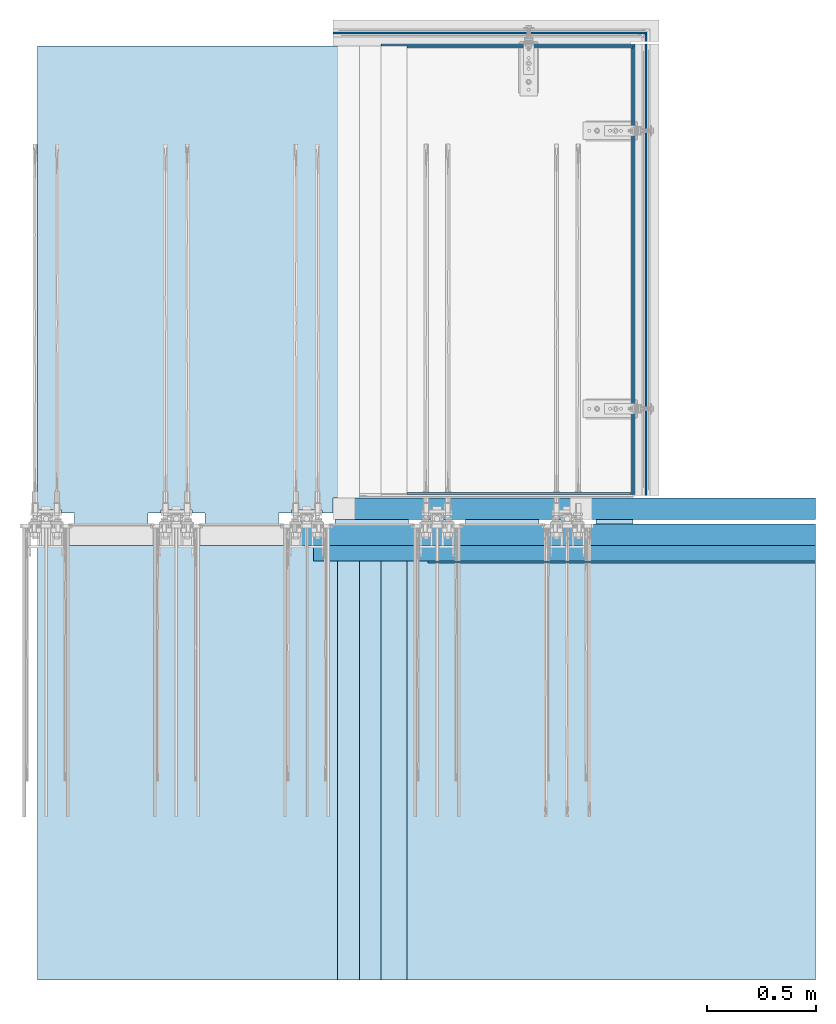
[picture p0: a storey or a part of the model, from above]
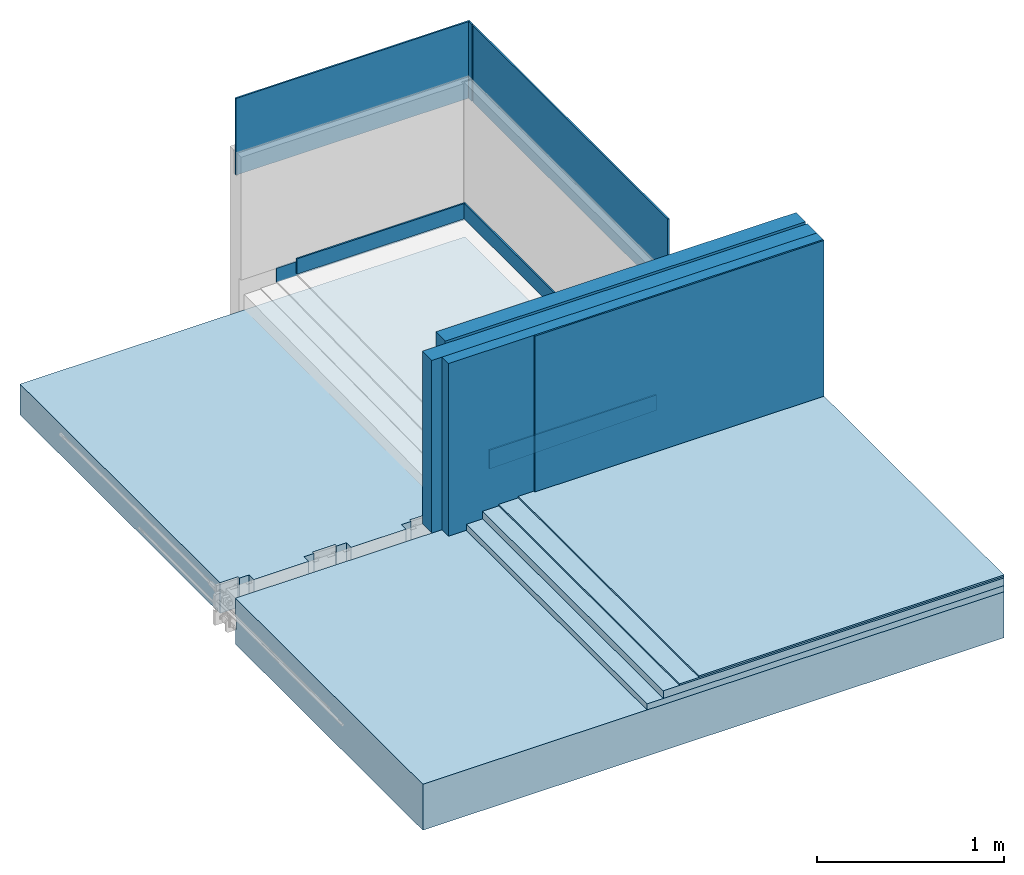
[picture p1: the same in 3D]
Properties of the parts of a building model (IFC2X3), part 1 of 2

# File
Description: ViewDefinition [CoordinationView_V2.0, QuantityTakeOffAddOnView], RevitIdentifiers [ContentGUID: 704ee8e6-b7a5-4cdf-b516-c9cadaf13e75, VersionGUID: 24b7fbaf-eea0-4a53-a88f-534976aedb0a, NumberOfSaves: 71], CoordinateReference [CoordinateBase: Shared Coordinates, ProjectSite: Internal]
File name: Solucion balcón prefabricado.ifc
Time: 2026-03-23T12:44:45+01:00
Written by: ODA SDAI 24.6
Made in: Autodesk Revit 24.3.40.26 (ESP) - IFC 24.3.20.0

# IfcProject, 000000
LongName: Solución de balcón prefabricado

# IfcSite, Default
RefLatitude: 40, 25, 13, 9643; RefLongitude: -3, -42, -20, -772056; RefElevation: 0 m
Otra - Categoría: Información de proyecto; Dirección de proyecto: Parque Empresarial de A Pontenova , Parcelas 33-39 , 27720 · A Pontenova · (Lugo); Fecha de emisión de proyecto: 13-02-2026; Nombre de cliente: Recense; Nombre de proyecto: Solución de balcón prefabricado; Número de proyecto: 000000
Datos de identidad - Autor: Deliprogal SL; Descripción de organización: Fijaciones a medida para prefabricado; Nombre de organización: Recense

# IfcBuilding
Pset_BuildingCommon - NumberOfStoreys: 1
Otra - Categoría: Información de proyecto; Dirección de proyecto: Parque Empresarial de A Pontenova , Parcelas 33-39 , 27720 · A Pontenova · (Lugo); Fecha de emisión de proyecto: 13-02-2026; Nombre de cliente: Recense; Nombre de proyecto: Solución de balcón prefabricado; Número de proyecto: 000000
Datos de identidad - Autor: Deliprogal SL; Descripción de organización: Fijaciones a medida para prefabricado; Nombre de organización: Recense

# IfcBuildingStorey: Nivel:8mm Head, L0
LongName: L0; Elevation: 0 m
Otra - Categoría: Niveles; Familia: Nivel; Familia y tipo: Nivel: 8mm Head; ID de tipo: 305; Tipo: 8mm Head
Restricciones - Elevación: 0 m
Cotas - Altura de cálculo: 0 m
Datos de identidad - Estructura: no; Nombre: L0; Planta de edificio: yes
Otra(Tipo) - Categoría: Niveles; Nombre de familia: Nivel
Restricciones(Tipo) - Base de elevación: Punto base del proyecto
Gráficos(Tipo) - Color: 12615680; Grosor de línea: 1; Patrón de línea: Dash dot; Símbolo en extremo 1 por defecto: no; Símbolo en extremo 2 por defecto: yes
Datos de identidad(Tipo) - Nombre de tipo: 8mm Head

# IfcBuildingElementProxy: Calzo termoplastico:Calzo termoplastico, Calzo termoplastico:Calzo termoplastico:3849835
In: L0
Type - Material: Caucho, butilo
Type - Otra - Categoría: Modelos genéricos; Nombre de familia: Calzo termoplastico
Type - Datos de identidad - Nombre de tipo: Calzo termoplastico
Pset_BuildingElementProxyCommon - Reference: Calzo termoplastico; sets with these values: 2
Otra - Familia: Calzo termoplastico; Familia y tipo: Calzo termoplastico: Calzo termoplastico; ID de tipo: 3849833; Tipo: Calzo termoplastico
Restricciones - Elevación desde el nivel: 0 m; Se mueve con elementos cercanos: no
Cotas - Área: 0.004 m2; Volumen: 0.0004 m3
Proceso por fases - Fase de creación: New

# IfcBuildingElementProxy: Modelos genéricos 2:Modelos genéricos 2, Modelos genéricos 2:Modelos genéricos 2:3888620
In: L0
Type - Material: Caucho, butilo
Type - Otra - Categoría: Modelos genéricos; Nombre de familia: Modelos genéricos 2
Type - Datos de identidad - Nombre de tipo: Modelos genéricos 2
Pset_BuildingElementProxyCommon - Reference: Modelos genéricos 2; sets with these values: 2
Otra - Familia: Modelos genéricos 2; Familia y tipo: Modelos genéricos 2: Modelos genéricos 2; ID de tipo: 3888618; Tipo: Modelos genéricos 2
Restricciones - Elevación desde el nivel: 0 m; Se mueve con elementos cercanos: no
Cotas - Área: 0.0347063 m2; Volumen: 0.000767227 m3
Proceso por fases - Fase de creación: New

# IfcBuildingElementProxy: Panel Hormigón 2:Panel Hormigón, Panel Hormigón 2:Panel Hormigón:3863525
In: L0
Type - Material: Aislamiento semirrígido, Hormigón panel
Type - Otra - Categoría: Modelos genéricos; Nombre de familia: Panel Hormigón 2
Type - Restricciones - Elevación por defecto: 13.1234 m
Type - Datos de identidad - Nombre de tipo: Panel Hormigón
Pset_BuildingElementProxyCommon - Reference: Panel Hormigón; sets with these values: 2
Otra - Familia: Panel Hormigón 2; Familia y tipo: Panel Hormigón 2: Panel Hormigón; ID de tipo: 3863828; Tipo: Panel Hormigón
Restricciones - Nivel: L0; Nivel de tabla de planificación: L0; Desfase desde el anfitrión: -0.5 m; Elevación desde el nivel: -0.5 m; Plano de trabajo: Nivel : L0
Cotas - Área: 5.91826 m2; Volumen: 0.239555 m3
Proceso por fases - Fase de creación: New

# IfcBuildingElementProxy: Panel Hormigón:Panel Hormigón, Panel Hormigón:Panel Hormigón:3880171
In: L0
Type - Material: Hormigón panel
Type - Otra - Categoría: Modelos genéricos; Nombre de familia: Panel Hormigón
Type - Restricciones - Elevación por defecto: 13.1234 m
Type - Datos de identidad - Nombre de tipo: Panel Hormigón
Pset_BuildingElementProxyCommon - Reference: Panel Hormigón; sets with these values: 2
Otra - Tipo: Panel Hormigón; Familia: Panel Hormigón; Familia y tipo: Panel Hormigón: Panel Hormigón; ID de tipo: 3880099
Restricciones - Nivel: L0; Nivel de tabla de planificación: L0; Desfase desde el anfitrión: -0.5 m; Elevación desde el nivel: -0.5 m; Plano de trabajo: Nivel : L0
Cotas - Área: 3.84907 m2; Volumen: 0.334839 m3
Proceso por fases - Fase de creación: New

# IfcBuildingElementProxy: Placa de separación:FBAIGCEQ (4)
In: L0
Type - Material: REC_Acero, S 275JR (Zincado)
Type - Otra - Categoría: Modelos genéricos; Nombre de familia: Placa de separación
Type - Restricciones - Elevación por defecto: 13.1234 m
Type - Datos de identidad - Creado por:: Deliprogal; Descripción: Spacer plate; Description_ESP: Placa de separación; Fabricante: RECENSE; Fecha de Creacion:: 11/02/2026; Fecha Ultima Revision:: 12/02/2026; Modelo: Placa de separación; Nombre de tipo: FBAIGCEQ; URL: https://prefabricados.recense.com/documentacion/prefabricados/doc/Fijacion_balcones.pdf
Type - Pset_ManufacturerTypeInformation - Manufacturer: RECENSE
Pset_BuildingElementProxyCommon - Reference: FBAIGCEQ; sets with these values: 2
Otra - Tipo: FBAIGCEQ; Familia: Placa de separación; Familia y tipo: Placa de separación: FBAIGCEQ; ID de tipo: 3812632
Restricciones - Se mueve con elementos cercanos: no; Anfitrión: Ninguno; Desfase desde el anfitrión: -0.1 m; Elevación desde el nivel: -0.1 m
Cotas - Área: 0.0223554 m2; Volumen: 0.000149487 m3
Proceso por fases - Fase de creación: New
Name (Placa de separación:FBAIGCEQ:...)
3935560
3935673
3935674
3935675

# IfcBuildingElementProxy: Sellado:Sellado, Sellado:Sellado:3863577
In: L0
Type - Material: Caucho, butilo
Type - Otra - Categoría: Modelos genéricos; Nombre de familia: Sellado
Type - Datos de identidad - Nombre de tipo: Sellado
Pset_BuildingElementProxyCommon - Reference: Sellado; sets with these values: 2
Otra - Familia: Sellado; Familia y tipo: Sellado: Sellado; ID de tipo: 3863575; Tipo: Sellado
Restricciones - Se mueve con elementos cercanos: no
Cotas - Área: 0.618212 m2; Volumen: 0.0121574 m3
Proceso por fases - Fase de creación: New

# IfcElementAssembly: GEN-A-M12:A-M12 (3)
In: L0
Type - Material: REC_Acero, S 275JR (Zincado)
Type - Otra - Categoría: Conexiones estructurales; Nombre de familia: GEN-A-M12
Type - Restricciones - Elevación por defecto: 0 m
Type - Datos - Classification.Uniclass.Pr.Description: Bolts and accessories; Classification.Uniclass.Pr.Number: Pr_20_29_08
Type - Datos de identidad - Código de montaje: Tornillo perfil hormigón M12x50 mm (8.8); Costo: 0; Creado por:: Deliprogal SL; Descripción: Arandela M12; Description_ESP: Concrete profile screw M12x50 mm (8.8); Fabricante: RECENSE; Fecha de Creacion:: 09/11/2025; Fecha Ultima Revision:: 12/02/2026; Keynote_ESP: Screw for fixing elements to the concrete profile PH4022; Modelo: TPH1250; Nombre de tipo: A-M12; Nota clave: Tornillo para fijar elementos al Perfil de Hormigón PH4022; URL: https://prefabricados.recense.com/prefabricados/fijacion/fijacion-antivuelco-hormigon/tph/
Classification: Tornillo perfil hormigón M12x50 mm (8.8) (Uniformat)
Pset_QuantityTakeOff - Reference: A-M12
Otra - Familia: GEN-A-M12; Familia y tipo: GEN-A-M12: A-M12; ID de tipo: 3863805; Tipo: A-M12
Restricciones - Se mueve con elementos cercanos: no
Datos - DPG_FABRICA: IL; DPG_NUMERO_OT: OT-
Cotas - Área: 0.000441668 m2; Volumen: 7.16248e-07 m3
Proceso por fases - Fase de creación: New
Name (GEN-A-M12:A-M12:...) | Anfitrión
3863552 | Panel Hormigón 2 : Panel Hormigón
3884091 | Panel Hormigón : Panel Hormigón
3884166 | Panel Hormigón : Panel Hormigón

# IfcElementAssembly: GEN-T-M12:T-M12 (3)
In: L0
Type - Material: REC_Acero, S 275JR (Zincado)
Type - Otra - Categoría: Conexiones estructurales; Nombre de familia: GEN-T-M12
Type - Restricciones - Elevación por defecto: 0 m
Type - Datos - Classification.Uniclass.Pr.Description: Bolts and accessories; Classification.Uniclass.Pr.Number: Pr_20_29_08
Type - Datos de identidad - Costo: 0; Creado por:: Deliprogal SL; Descripción: Concrete profile screw M12x50 mm (8.8); Description_ESP: Tornillo perfil hormigón M12x50 mm (8.8).; Fabricante: FERRETERÍA; Fecha de Creacion:: 01/03/2024; Fecha Ultima Revision:: 01/03/2024; Keynote_ESP: Screw for fixing elements to the concrete profile PH4022.; Modelo: TPH1250; Nombre de tipo: T-M12; Nota clave: Tornillo para fijar elementos al Perfil de Hormigón PH4022.; URL: https://prefabricados.recense.com/prefabricados/fijacion/fijacion-antivuelco-hormigon/tph/
Pset_QuantityTakeOff - Reference: T-M12
Otra - Familia: GEN-T-M12; Familia y tipo: GEN-T-M12: T-M12; ID de tipo: 3863804; Tipo: T-M12
Restricciones - Se mueve con elementos cercanos: no
Cotas - Área: 0.000789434 m2; Volumen: 0.00000247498 m3
Proceso por fases - Fase de creación: New
Name (GEN-T-M12:T-M12:...) | Anfitrión
3863553 | Panel Hormigón 2 : Panel Hormigón
3884092 | Panel Hormigón : Panel Hormigón
3884167 | Panel Hormigón : Panel Hormigón

# IfcElementAssembly: REC-A-M16:A-M16 (3)
In: L0
Type - Material: REC_Acero, S 275JR (Zincado)
Type - Otra - Categoría: Conexiones estructurales; Nombre de familia: REC-A-M16
Type - Restricciones - Elevación por defecto: 0 m
Type - Datos - Classification.Uniclass.Pr.Description: Bolts and accessories; Classification.Uniclass.Pr.Number: Pr_20_29_08
Type - Datos de identidad - Costo: 0; Creado por:: Deliprogal SL; Descripción: Arandela M16; Fabricante: RECENSE; Fecha de Creacion:: 01/03/2024; Fecha Ultima Revision:: 01/03/2024; Modelo: A-M16; Nombre de tipo: A-M16; URL: https://recense.com/
Pset_QuantityTakeOff - Reference: A-M16
Otra - Familia: REC-A-M16; Familia y tipo: REC-A-M16: A-M16; ID de tipo: 3863823; Tipo: A-M16
Restricciones - Se mueve con elementos cercanos: no
Datos - DPG_FABRICA: IL; DPG_NUMERO_OT: OT-
Cotas - Área: 0.000701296 m2; Volumen: 0.00000143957 m3
Proceso por fases - Fase de creación: New
Name (REC-A-M16:A-M16:...) | Anfitrión
3863529 | Panel Hormigón 2 : Panel Hormigón
3884332 | Panel Hormigón : Panel Hormigón
3884951 | Panel Hormigón : Panel Hormigón

# IfcElementAssembly: REC-AEM12-100:AEM12-100 (3)
In: L0
Type - Material: REC_Acero, S 275JR (Zincado)
Type - Otra - Categoría: Conexiones estructurales; Nombre de familia: REC-AEM12-100
Type - Restricciones - Elevación por defecto: 0 m
Type - Datos - Classification.Uniclass.Pr.Description: Bolts and accessories; Classification.Uniclass.Pr.Number: Pr_20_29_08
Type - Datos de identidad - Costo: 0; Creado por:: Deliprogal SL; Descripción: Anclaje M12; Fabricante: RECENSE; Fecha de Creacion:: 01/03/2024; Fecha Ultima Revision:: 16/03/2026; Modelo: AEM12-100; Nombre de tipo: AEM12-100; URL: https://recense.com/
Pset_QuantityTakeOff - Reference: AEM12-100
Otra - Familia: REC-AEM12-100; Familia y tipo: REC-AEM12-100: AEM12-100; ID de tipo: 3863814; Tipo: AEM12-100
Restricciones - Se mueve con elementos cercanos: no
Datos - DPG_FABRICA: IL; DPG_NUMERO_OT: OT-
Cotas - Área: 0.00338965 m2; Volumen: 0.0000142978 m3
Proceso por fases - Fase de creación: New
Name (REC-AEM12-100:AEM12-100:...) | Anfitrión
3863551 | Panel Hormigón 2 : Panel Hormigón
3884090 | Panel Hormigón : Panel Hormigón
3884165 | Panel Hormigón : Panel Hormigón

# IfcElementAssembly: REC-AEM12-140:AEM12-140 (3)
In: L0
Type - Material: REC_Acero, S 275JR (Zincado)
Type - Otra - Categoría: Conexiones estructurales; Nombre de familia: REC-AEM12-140
Type - Restricciones - Elevación por defecto: 0 m
Type - Datos - Classification.Uniclass.Pr.Description: Bolts and accessories; Classification.Uniclass.Pr.Number: Pr_20_29_08
Type - Datos de identidad - Costo: 0; Creado por:: Deliprogal SL; Descripción: Anclaje M12; Fabricante: GENERICO; Fecha de Creacion:: 07/11/2025; Fecha Ultima Revision:: 16/03/2026; Modelo: AEM12-140; Nombre de tipo: AEM12-140; URL: https://recense.com/
Pset_QuantityTakeOff - Reference: AEM12-140
Otra - Familia: REC-AEM12-140; Familia y tipo: REC-AEM12-140: AEM12-140; ID de tipo: 3863817; Tipo: AEM12-140
Restricciones - Se mueve con elementos cercanos: no
Cotas - Área: 0.00414363 m2; Volumen: 0.0000188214 m3
Proceso por fases - Fase de creación: New
Name (REC-AEM12-140:AEM12-140:...) | Anfitrión
3863531 | Panel Hormigón 2 : Panel Hormigón
3884334 | Panel Hormigón : Panel Hormigón
3884953 | Panel Hormigón : Panel Hormigón

# IfcElementAssembly: REC-CPA448T17:CPA448T17 (3)
In: L0
Type - Material: REC_Acero, S 275JR (Zincado)
Type - Otra - Categoría: Conexiones estructurales; Nombre de familia: REC-CPA448T17
Type - Restricciones - Elevación por defecto: 0 m
Type - Datos - Classification.Uniclass.Pr.Description: Plate (square) washers; Classification.Uniclass.Pr.Number: Pr_20_29_60_63
Type - Datos de identidad - Costo: 0; Creado por:: Deliprogal SL; Descripción: Contraplaca antideslizante; Fabricante: RECENSE; Fecha de Creacion:: 10/11/2025; Fecha Ultima Revision:: 16/03/2026; Modelo: CPA448T17; Nombre de tipo: CPA448T17; URL: https://prefabricados.recense.com/prefabricados/fijacion/fijacion-antivuelco-hormigon/para2501208rt/
Pset_QuantityTakeOff - Reference: CPA448T17
Otra - Familia: REC-CPA448T17; Familia y tipo: REC-CPA448T17: CPA448T17; ID de tipo: 3863801; Tipo: CPA448T17
Restricciones - Se mueve con elementos cercanos: no
Datos - DPG_FABRICA: IL; DPG_NUMERO_OT: OT-
Cotas - Área: 0.00433573 m2; Volumen: 0.0000136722 m3
Proceso por fases - Fase de creación: New
Name (REC-CPA448T17:CPA448T17:...) | Anfitrión
3863582 | Ninguno
3884335 | Panel Hormigón : Panel Hormigón
3884954 | Panel Hormigón : Panel Hormigón

# IfcElementAssembly: REC-HBP M16-75 EV:HBP M16-75 EV (3)
In: L0
Type - Material: REC_Acero, S 275JR (Zincado)
Type - Otra - Categoría: Conexiones estructurales; Nombre de familia: REC-HBP M16-75 EV
Type - Restricciones - Elevación por defecto: 0 m
Type - Datos - Classification.Uniclass.Pr.Description: Lifting anchors; Classification.Uniclass.Pr.Number: Pr_20_29_03_47
Type - Datos de identidad - Costo: 0; Creado por:: Deliprogal SL; Descripción: Casquillo fijación HBP; Description_ESP: CASQUILLO; Fabricante: RECENSE; Fecha de Creacion:: 07/11/2025; Fecha Ultima Revision:: 06/02/2026; Keynote_ESP: Casquillo e insertos roscados hembra para dejar embebidos en los prefabricados de hormigón y ser usados posteriormente para su fijación a la estructura del edificio, o para la instalación de elementos auxiliares.; Modelo: HBP M16x75 EV; Nombre de tipo: HBP M16-75 EV; Nota clave: Female threaded sleeves and inserts designed to be embedded in precast concrete elements and later used for fastening them to the building structure or for installing auxiliary components.; URL: https://prefabricados.recense.com/prefabricados/fijacion/casquillos-estandar/
Pset_QuantityTakeOff - Reference: HBP M16-75 EV
Otra - Familia: REC-HBP M16-75 EV; Familia y tipo: REC-HBP M16-75 EV: HBP M16-75 EV; ID de tipo: 3863803; Tipo: HBP M16-75 EV
Restricciones - Se mueve con elementos cercanos: no
Cotas - Área: 0.00790422 m2; Volumen: 0.0000329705 m3
Proceso por fases - Fase de creación: New
Estructura - Recubrimiento de armadura: Rebar Cover 1 <25 mm>
Name (REC-HBP M16-75 EV:HBP M16-75 EV:...) | Anfitrión
3863528 | Panel Hormigón 2 : Panel Hormigón
3884331 | Panel Hormigón : Panel Hormigón
3884950 | Panel Hormigón : Panel Hormigón

# IfcElementAssembly: REC-M16-45:M16-45 (3)
In: L0
Type - Material: REC_Acero, S 275JR (Zincado)
Type - Otra - Categoría: Conexiones estructurales; Nombre de familia: REC-M16-45
Type - Restricciones - Elevación por defecto: 0 m
Type - Datos - Classification.Uniclass.Pr.Description: Bolts and accessories; Classification.Uniclass.Pr.Number: Pr_20_29_08
Type - Datos de identidad - Costo: 0; Creado por:: Deliprogal SL; Descripción: Tornillo M16 L=45; Fabricante: RECENSE; Fecha de Creacion:: 01/03/2024; Fecha Ultima Revision:: 01/03/2024; Modelo: M16-45; Nombre de tipo: M16-45; URL: https://recense.com/
Pset_QuantityTakeOff - Reference: M16-45
Otra - Familia: REC-M16-45; Familia y tipo: REC-M16-45: M16-45; ID de tipo: 3863822; Tipo: M16-45
Restricciones - Se mueve con elementos cercanos: no
Datos - DPG_FABRICA: IL; DPG_NUMERO_OT: OT-
Cotas - Área: 0.00240261 m2; Volumen: 0.0000157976 m3
Proceso por fases - Fase de creación: New
Name (REC-M16-45:M16-45:...) | Anfitrión
3863530 | Panel Hormigón 2 : Panel Hormigón
3884333 | Panel Hormigón : Panel Hormigón
3884952 | Panel Hormigón : Panel Hormigón

# IfcElementAssembly: REC-M16-60:M16-60 (5)
In: L0
Type - Material: REC_Acero, S 275JR (Zincado)
Type - Otra - Categoría: Conexiones estructurales; Nombre de familia: REC-M16-60
Type - Restricciones - Elevación por defecto: 0 m
Type - Datos - Classification.Uniclass.Pr.Description: Bolts and accessories; Classification.Uniclass.Pr.Number: Pr_20_29_08
Type - Datos de identidad - Costo: 0; Creado por:: Deliprogal SL; Descripción: Tornillo M16 L=60; Fabricante: RECENSE; Fecha de Creacion:: 01/03/2024; Fecha Ultima Revision:: 23/03/2025; Modelo: M16-60; Nombre de tipo: M16-60; URL: https://prefabricados.recense.com/prefabricados/fijacion-de-balcones-prefabricados/
Pset_QuantityTakeOff - Reference: M16-60
Otra - Familia: REC-M16-60; Familia y tipo: REC-M16-60: M16-60; ID de tipo: 3934453; Tipo: M16-60
Restricciones - Se mueve con elementos cercanos: no; Anfitrión: Suelo : DPG_Balcon_Prefabricado
Datos - DPG_FABRICA: IL; DPG_NUMERO_OT: OT-
Cotas - Área: 0.00265237 m2; Volumen: 0.0000172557 m3
Proceso por fases - Fase de creación: New
Name (REC-M16-60:M16-60:...)
3799158
3825876
3825932
3825964
3839076

# IfcElementAssembly: REC-M20-60:M20-60 (10)
In: L0
Type - Material: REC_Acero, S 275JR (Zincado)
Type - Otra - Categoría: Conexiones estructurales; Nombre de familia: REC-M20-60
Type - Restricciones - Elevación por defecto: 0 m
Type - Datos - Classification.Uniclass.Pr.Description: Bolts and accessories; Classification.Uniclass.Pr.Number: Pr_20_29_08
Type - Datos de identidad - Costo: 0; Creado por:: Deliprogal SL; Descripción: M20 bolt, L = 50 mm; Description_ESP: Tornillo M20 L=50; Fabricante: RECENSE; Fecha de Creacion:: 01/03/2024; Fecha Ultima Revision:: 23/03/2024; Modelo: M20-60; Nombre de tipo: M20-60; URL: https://prefabricados.recense.com/prefabricados/fijacion-de-balcones-prefabricados/
Pset_QuantityTakeOff - Reference: M20-60
Otra - Familia: REC-M20-60; Familia y tipo: REC-M20-60: M20-60; ID de tipo: 3934460; Tipo: M20-60
Restricciones - Se mueve con elementos cercanos: no; Anfitrión: Suelo : DPG_Balcon_Prefabricado
Cotas - Área: 0.003654 m2; Volumen: 0.0000289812 m3
Proceso por fases - Fase de creación: New
Name (REC-M20-60:M20-60:...)
3799154
3799155
3825872
3825873
3825928
3825929
3825960
3825961
3839072
3839073

# IfcElementAssembly: REC-PAA150708T14:PAA150708T14 (3)
In: L0
Type - Material: REC_Acero, S 275JR (Zincado)
Type - Otra - Categoría: Conexiones estructurales; Nombre de familia: REC-PAA150708T14
Type - Restricciones - Elevación por defecto: 0 m
Type - Datos - Classification.Uniclass.Pr.Description: Carbon steel anchor plates; Classification.Uniclass.Pr.Number: Pr_20_29_03_10
Type - Datos de identidad - Costo: 0; Creado por:: Deliprogal SL; Descripción: Non-slip angle plate 150x70x50x8, with 3 holes Ø14 mm on one side and hole Ø14 mm on another side.; Description_ESP: Pletina angular antideslizante 150x70x50x8 mm, 3 taladros TØ14 mm en un ala y TØ14 mm en la otra.; Fabricante: RECENSE; Fecha de Creacion:: 01/11/2025; Fecha Ultima Revision:: 06/02/2025; Keynote_ESP: Anclaje antivuelco para fijación de paneles a estructura de hormigón mediante la interposición de perfiles y/ó tornillos de anclaje expansivo.; Modelo: PAA150708T14; Nombre de tipo: PAA150708T14; Nota clave: Anti-tilt anchor for fixing panels to concrete structures by means of interposing profiles and/or expansion anchor bolts.; URL: https://prefabricados.recense.com/prefabricados/fijacion/fijacion-antivuelco-hormigon/paaxxx708t14/
Type - Visibilidad - Visible: yes
Pset_QuantityTakeOff - Reference: PAA150708T14
Otra - Familia: REC-PAA150708T14; Familia y tipo: REC-PAA150708T14: PAA150708T14; ID de tipo: 3863806; Tipo: PAA150708T14
Restricciones - Se mueve con elementos cercanos: no
Cotas - Área: 0.0125849 m2; Volumen: 0.0000785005 m3
Proceso por fases - Fase de creación: New
Name (REC-PAA150708T14:PAA150708T14:...) | Anfitrión
3863579 | Ninguno
3884089 | Panel Hormigón : Panel Hormigón
3884164 | Panel Hormigón : Panel Hormigón

# IfcElementAssembly: REC-PARA2501208RT:PARA2501208RT (3)
In: L0
Type - Material: REC_Acero, S 275JR (Zincado)
Type - Otra - Categoría: Conexiones estructurales; Nombre de familia: REC-PARA2501208RT
Type - Restricciones - Elevación por defecto: 0 m
Type - Datos - Classification.Uniclass.Pr.Description: Brackets; Classification.Uniclass.Pr.Number: Pr_20_85_09
Type - Datos de identidad - Costo: 0; Creado por:: Deliprogal SL; Descripción: Pletina reforzada PARA; Fabricante: RECENSE; Fecha de Creacion:: 8/11/2025; Fecha Ultima Revision:: 16/03/2026; Modelo: PARA2501208RT; Nombre de tipo: PARA2501208RT; URL: https://prefabricados.recense.com/prefabricados/fijacion/fijacion-antivuelco-hormigon/para2501208rt/
Pset_QuantityTakeOff - Reference: PARA2501208RT
Otra - Familia: REC-PARA2501208RT; Familia y tipo: REC-PARA2501208RT: PARA2501208RT; ID de tipo: 3863802; Tipo: PARA2501208RT
Restricciones - Se mueve con elementos cercanos: no
Cotas - Área: 0.0616333 m2; Volumen: 0.000369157 m3
Proceso por fases - Fase de creación: New
Name (REC-PARA2501208RT:PARA2501208RT:...) | Anfitrión
3863583 | Ninguno
3884336 | Panel Hormigón : Panel Hormigón
3884955 | Panel Hormigón : Panel Hormigón

# IfcElementAssembly: REC-PH4022:PH4022 (3)
In: L0
Type - Material: REC_Acero, S 275JR (Zincado)
Type - Otra - Categoría: Conexiones estructurales; Nombre de familia: REC-PH4022
Type - Restricciones - Elevación por defecto: 0 m
Type - Datos - Classification.Uniclass.Pr.Description: Carbon steel cast-in channels; Classification.Uniclass.Pr.Number: Pr_20_85_84_11
Type - Datos de identidad - Costo: 0; Creado por:: Deliprogal SL; Descripción: Concrete profile 150x67x40x22x22x2.5 mm.; Description_ESP: Perfil hormigón 150x67x40x22x2.5 mm.; Fabricante: RECENSE; Fecha de Creacion:: 10/11/2025; Fecha Ultima Revision:: 06/02/2026; Keynote_ESP: Perfil para dejar embebido en elementos de hormigón para su posterior fijación mediante Tornillos de Perfil de Hormigón TPH y el anclaje correspondiente.; Modelo: PH4022; Nombre de tipo: PH4022; Nota clave: Profile to be embedded in concrete elements for subsequent fixing by means of TPH Concrete Profile Screws and the corresponding anchorage.; URL: https://prefabricados.recense.com/prefabricados/fijacion/fijacion-antivuelco-hormigon/ph4022/
Pset_QuantityTakeOff - Reference: PH4022
Otra - Familia: REC-PH4022; Familia y tipo: REC-PH4022: PH4022; ID de tipo: 3863807; Tipo: PH4022
Restricciones - Se mueve con elementos cercanos: no
Cotas - Área: 0.016689 m2; Volumen: 0.0000420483 m3
Proceso por fases - Fase de creación: New
Name (REC-PH4022:PH4022:...) | Anfitrión
3863549 | Panel Hormigón 2 : Panel Hormigón
3884087 | Panel Hormigón : Panel Hormigón
3884162 | Panel Hormigón : Panel Hormigón

# IfcElementAssembly: REC-T-M20:T_M20 (10)
In: L0
Type - Material: REC_Acero, S 275JR (Zincado)
Type - Otra - Categoría: Conexiones estructurales; Nombre de familia: REC-T-M20
Type - Restricciones - Elevación por defecto: 0 m
Type - Datos - Classification.Uniclass.Pr.Description: Bolts and accessories; Classification.Uniclass.Pr.Number: Pr_20_29_08
Type - Datos de identidad - Costo: 0; Creado por:: Deliprogal SL; Descripción: M20 washer; Description_ESP: ARANDELA M20; Fabricante: RECENSE; Fecha de Creacion:: 12/02/2026; Fecha Ultima Revision:: 23/03/2026; Modelo: A_M20; Nombre de tipo: T_M20; URL: https://prefabricados.recense.com/prefabricados/fijacion-de-balcones-prefabricados/
Pset_QuantityTakeOff - Reference: T_M20
Otra - Familia: REC-T-M20; Familia y tipo: REC-T-M20: T_M20; ID de tipo: 3934461; Tipo: T_M20
Restricciones - Se mueve con elementos cercanos: no; Anfitrión: Suelo : DPG_Balcon_Prefabricado
Datos - DPG_FABRICA: IL; DPG_NUMERO_OT: OT
Cotas - Área: 0.00100207 m2; Volumen: 0.00000218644 m3
Proceso por fases - Fase de creación: New
Name (REC-T-M20:T_M20:...)
3799152
3799153
3825870
3825871
3825926
3825927
3825958
3825959
3839070
3839071

# IfcElementAssembly: REC-TPH1250:TPH1250 (3)
In: L0
Type - Material: REC_Acero, S 275JR (Zincado)
Type - Otra - Categoría: Conexiones estructurales; Nombre de familia: REC-TPH1250
Type - Restricciones - Elevación por defecto: 0 m
Type - Datos - Classification.Uniclass.Pr.Description: Bolts and accessories; Classification.Uniclass.Pr.Number: Pr_20_29_08
Type - Datos de identidad - Costo: 0; Creado por:: Deliprogal SL; Descripción: Concrete profile screw M12x50 mm (8.8); Description_ESP: Tornillo perfil hormigón M12x50 mm (8.8).; Fabricante: RECENSE; Fecha de Creacion:: 9/11/2025; Fecha Ultima Revision:: 06/02/2026; Keynote_ESP: Tornillo para fijar elementos al Perfil de Hormigón PH4022.; Modelo: TPH1250; Nombre de tipo: TPH1250; Nota clave: Screw for fixing elements to the concrete profile PH4022.; URL: https://prefabricados.recense.com/prefabricados/fijacion/fijacion-antivuelco-hormigon/tph/
Pset_QuantityTakeOff - Reference: TPH1250
Otra - Familia: REC-TPH1250; Familia y tipo: REC-TPH1250: TPH1250; ID de tipo: 3863800; Tipo: TPH1250
Restricciones - Se mueve con elementos cercanos: no
Cotas - Área: 0.00199136 m2; DPG_PosicionTuerca: 0.015 m; Volumen: 0.00000937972 m3
Proceso por fases - Fase de creación: New
Name (REC-TPH1250:TPH1250:...) | Anfitrión
3863550 | Panel Hormigón 2 : Panel Hormigón
3884088 | Panel Hormigón : Panel Hormigón
3884163 | Panel Hormigón : Panel Hormigón

# IfcFurnishingElement: Elemento de regulación:Elemento de regulación (5)
In: L0
Type - Material: REC_Acero, S 275JR (Zincado)
Type - Otra - Categoría: Conexiones estructurales; Nombre de familia: Elemento de regulación
Type - Restricciones - Elevación por defecto: 13.1234 m
Type - Datos de identidad - Creado por:: Deliprogal SL; Descripción: Adjustment system; Description_ESP: Sistema de regulación; Fabricante: RECENSE; Fecha de Creacion:: 11/02/2026; Fecha Ultima Revision:: 12/02/2026; Modelo: Elemento Regulación; Nombre de tipo: Elemento de regulación; URL: https://prefabricados.recense.com/prefabricados/fijacion-de-balcones-prefabricados/
Type - Pset_ManufacturerTypeInformation - Manufacturer: RECENSE
Pset_QuantityTakeOff - Reference: Elemento de regulación
Otra - Familia: Elemento de regulación; Familia y tipo: Elemento de regulación: Elemento de regulación; ID de tipo: 3934454; Tipo: Elemento de regulación
Restricciones - Se mueve con elementos cercanos: no; Anfitrión: Suelo : DPG_Balcon_Prefabricado; Desfase desde el anfitrión: -0.000773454 m
Cotas - Área: 0.0144948 m2; Volumen: 0.000118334 m3
Proceso por fases - Fase de creación: New
Estructura - Recubrimiento de armadura: Rebar Cover 1 <25 mm>
Name (Elemento de regulación:Elemento de regulación:...)
3799159
3825877
3825933
3825965
3839077

# IfcFurnishingElement: REC_FBAB200GC:FBAB200GC (5)
In: L0
Type - Material: REC_Acero, S 275JR (Zincado)
Type - Otra - Categoría: Conexiones estructurales; Nombre de familia: REC_FBAB200GC
Type - Restricciones - Elevación por defecto: 13.1234 m
Type - Datos de identidad - Creado por:: Deliprogal SL; Descripción: Balcony slab; Description_ESP: Placa de balcón; Fabricante: RECENSE; Fecha de Creacion:: 11/02/2026; Fecha Ultima Revision:: 23/03/2026; Modelo: FBAB200G; Nombre de tipo: FBAB200GC; URL: https://prefabricados.recense.com/prefabricados/fijacion-de-balcones-prefabricados/
Type - Pset_ManufacturerTypeInformation - Manufacturer: RECENSE
Pset_QuantityTakeOff - Reference: FBAB200GC
Otra - Familia: REC_FBAB200GC; Familia y tipo: REC_FBAB200GC: FBAB200GC; ID de tipo: 3934457; Tipo: FBAB200GC
Resultados de análisis - DPG_FOR_REG: 0.1523 m
Restricciones - Anfitrión: Suelo : DPG_Balcon_Prefabricado; Desfase desde el anfitrión: -0.116477 m; Se mueve con elementos cercanos: no
Cotas - Área: 0.211549 m2; DPG_REG: 0 m; Volumen: 0.0018954 m3
Proceso por fases - Fase de creación: New
Estructura - Recubrimiento de armadura: Rebar Cover 1 <25 mm>
Name (REC_FBAB200GC:FBAB200GC:...)
3799149
3825867
3825923
3825955
3839067

# IfcFurnishingElement: REC_FBAF200GC:FBAF200GC (5)
In: L0
Type - Material: REC_Acero, S 275JR (Zincado)
Type - Otra - Categoría: Conexiones estructurales; Nombre de familia: REC_FBAF200GC
Type - Restricciones - Elevación por defecto: 13.1234 m
Type - Datos de identidad - Creado por:: Deliprogal SL; Descripción: Placa de forjado; Fabricante: RECENSE; Fecha de Creacion:: 11/02/2026; Fecha Ultima Revision:: 23/03/2026; Modelo: FBAF200GC; Nombre de tipo: FBAF200GC; URL: https://prefabricados.recense.com/prefabricados/fijacion-de-balcones-prefabricados/
Type - Pset_ManufacturerTypeInformation - Manufacturer: RECENSE
Pset_QuantityTakeOff - Reference: FBAF200GC
Otra - Familia: REC_FBAF200GC; Familia y tipo: REC_FBAF200GC: FBAF200GC; ID de tipo: 3934458; Tipo: FBAF200GC
Restricciones - Se mueve con elementos cercanos: no; Anfitrión: Suelo : DPG_Balcon_Prefabricado; Desfase desde el anfitrión: 0.002 m
Proceso por fases - Fase de creación: New
Estructura - Recubrimiento de armadura: Rebar Cover 1 <25 mm>
Name (REC_FBAF200GC:FBAF200GC:...) | Área (m2) | Volumen (m3)
3799150 | 0.303429 | 0.00255947
3825868 | 0.303431 | 0.00255948
3825924 | 0.303431 | 0.00255948
3825956 | 0.303431 | 0.00255948
3839068 | 0.303435 | 0.00255963

# IfcFurnishingElement: REC_FBAIGCEQ:FBAIGCEQ (5)
In: L0
Type - Material: REC_Acero, S 275JR (Zincado)
Type - Otra - Categoría: Conexiones estructurales; Nombre de familia: REC_FBAIGCEQ
Type - Restricciones - Elevación por defecto: 13.1234 m
Type - Datos de identidad - Creado por:: Deliprogal SL; Descripción: Intermediate support; Description_ESP: Soporte intermedio; Fabricante: RECENSE; Fecha de Creacion:: 11/02/2026; Fecha Ultima Revision:: 23/03/2026; Modelo: FBAIGCEQ; Nombre de tipo: FBAIGCEQ; URL: https://prefabricados.recense.com/prefabricados/fijacion-de-balcones-prefabricados/
Type - Pset_ManufacturerTypeInformation - Manufacturer: RECENSE
Pset_QuantityTakeOff - Reference: FBAIGCEQ
Otra - Familia: REC_FBAIGCEQ; Familia y tipo: REC_FBAIGCEQ: FBAIGCEQ; ID de tipo: 3934459; Tipo: FBAIGCEQ
Restricciones - Se mueve con elementos cercanos: no; Anfitrión: Suelo : DPG_Balcon_Prefabricado; Desfase desde el anfitrión: -0.115703 m
Cotas - Área: 0.0174755 m2; Volumen: 0.000103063 m3
Proceso por fases - Fase de creación: New
Estructura - Recubrimiento de armadura: Rebar Cover 1 <25 mm>
Name (REC_FBAIGCEQ:FBAIGCEQ:...)
3799151
3825869
3825925
3825957
3839069

# IfcFurnishingElement: REC_P5067:REC_P5067 (10)
In: L0
Type - Material: REC_Acero, S 275JR (Zincado)
Type - Otra - Categoría: Conexiones estructurales; Nombre de familia: REC_P5067
Type - Restricciones - Elevación por defecto: 13.1234 m
Type - Datos de identidad - Creado por:: Deliprogal SL; Descripción: M24 coupling rod system.; Description_ESP: Sistema de varillas de acople M24; Fabricante: RECENSE; Fecha de Creacion:: 12/02/2026; Fecha Ultima Revision:: 23/03/2026; Modelo: REC_P5067; Nombre de tipo: REC_P5067; URL: https://prefabricados.recense.com/prefabricados/fijacion-de-balcones-prefabricados/
Type - Pset_ManufacturerTypeInformation - Manufacturer: RECENSE
Pset_QuantityTakeOff - Reference: REC_P5067
Otra - Familia: REC_P5067; Familia y tipo: REC_P5067: REC_P5067; ID de tipo: 3934463; Tipo: REC_P5067
Restricciones - Se mueve con elementos cercanos: no; Anfitrión: Suelo : DPG_Balcon_Prefabricado
Cotas - Área: 0.00539805 m2; Volumen: 0.0000482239 m3
Proceso por fases - Fase de creación: New
Estructura - Recubrimiento de armadura: Rebar Cover 1 <25 mm>
Name (REC_P5067:REC_P5067:...) | Desfase desde el anfitrión (m)
3799160 | -0.165703
3799166 | -0.0657034
3825878 | -0.165703
3825884 | -0.0657034
3825934 | -0.165703
3825940 | -0.0657034
3825966 | -0.165703
3825972 | -0.0657034
3839078 | -0.165703
3839084 | -0.0657034

# IfcFurnishingElement: REC_P5068:REC_P5068 (10)
In: L0
Type - Material: REC_Acero, S 275JR (Zincado)
Type - Otra - Categoría: Conexiones estructurales; Nombre de familia: REC_P5068
Type - Restricciones - Elevación por defecto: 13.1234 m
Type - Datos de identidad - Creado por:: Deliprogal SL; Descripción: M24 coupling rod system; Description_ESP: Sistema de varillas de acople M24; Fabricante: RECENSE; Fecha de Creacion:: 12/02/2026; Fecha Ultima Revision:: 23/03/2026; Modelo: P5068; Nombre de tipo: REC_P5068; URL: https://prefabricados.recense.com/prefabricados/fijacion-de-balcones-prefabricados/
Type - Pset_ManufacturerTypeInformation - Manufacturer: RECENSE
Pset_QuantityTakeOff - Reference: REC_P5068
Otra - Familia: REC_P5068; Familia y tipo: REC_P5068: REC_P5068; ID de tipo: 3934462; Tipo: REC_P5068
Restricciones - Se mueve con elementos cercanos: no; Anfitrión: Suelo : DPG_Balcon_Prefabricado
Cotas - Área: 0.00360783 m2; Volumen: 0.0000192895 m3
Proceso por fases - Fase de creación: New
Estructura - Recubrimiento de armadura: Rebar Cover 1 <25 mm>
Name (REC_P5068:REC_P5068:...) | Desfase desde el anfitrión (m)
3799161 | -0.05
3799167 | 0.05
3825879 | -0.05
3825885 | 0.05
3825935 | -0.05
3825941 | 0.05
3825967 | -0.05
3825973 | 0.05
3839079 | -0.05
3839085 | 0.05

# IfcFurnishingElement: REC_TCA_M24 8.8:REC_TCA_M24 8.8 (10)
In: L0
Type - Material: REC_Acero, S 275JR (Zincado)
Type - Otra - Categoría: Conexiones estructurales; Nombre de familia: REC_TCA_M24 8.8
Type - Restricciones - Elevación por defecto: 13.1234 m
Type - Datos de identidad - Creado por:: DELIPROGAL; Descripción: M24 coupling rod system; Description_ESP: Sistema de varillas de acople M24; Fabricante: RECENSE; Fecha de Creacion:: 12/02/2026; Fecha Ultima Revision:: 23/03/2026; Modelo: TCA_M24 8.8; Nombre de tipo: REC_TCA_M24 8.8; URL: https://prefabricados.recense.com/prefabricados/fijacion-de-balcones-prefabricados/
Type - Pset_ManufacturerTypeInformation - Manufacturer: RECENSE
Pset_QuantityTakeOff - Reference: REC_TCA_M24 8.8
Otra - Familia: REC_TCA_M24 8.8; Familia y tipo: REC_TCA_M24 8.8: REC_TCA_M24 8.8; ID de tipo: 3934550; Tipo: REC_TCA_M24 8.8
Restricciones - Se mueve con elementos cercanos: no; Anfitrión: Suelo : DPG_Balcon_Prefabricado
Cotas - Área: 0.00282118 m2; Volumen: 0.000014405 m3
Proceso por fases - Fase de creación: New
Estructura - Recubrimiento de armadura: Rebar Cover 1 <25 mm>
Name (REC_TCA_M24 8.8:REC_TCA_M24 8.8:...) | Desfase desde el anfitrión (m)
3799164 | -0.05
3799170 | 0.05
3825882 | -0.05
3825888 | 0.05
3825938 | -0.05
3825944 | 0.05
3825970 | -0.05
3825976 | 0.05
3839082 | -0.05
3839088 | 0.05

# IfcFurnishingElement: REC_TCA_M24:REC_TCA_M24 (20)
In: L0
Type - Material: REC_Acero, S 275JR (Zincado)
Type - Otra - Categoría: Conexiones estructurales; Nombre de familia: REC_TCA_M24
Type - Restricciones - Elevación por defecto: 13.1234 m
Type - Datos de identidad - Creado por:: Deliprogal SL; Descripción: M24 coupling rod system; Description_ESP: Sistema de varillas de acople M24; Fabricante: RECENSE; Fecha de Creacion:: 11/02/2026; Fecha Ultima Revision:: 23/03/2026; Modelo: TCA_M24; Nombre de tipo: REC_TCA_M24; URL: https://prefabricados.recense.com/prefabricados/fijacion-de-balcones-prefabricados/
Type - Pset_ManufacturerTypeInformation - Manufacturer: RECENSE
Pset_QuantityTakeOff - Reference: REC_TCA_M24
Otra - Familia: REC_TCA_M24; Familia y tipo: REC_TCA_M24: REC_TCA_M24; ID de tipo: 3934551; Tipo: REC_TCA_M24
Restricciones - Se mueve con elementos cercanos: no; Anfitrión: Suelo : DPG_Balcon_Prefabricado
Cotas - Área: 0.00187067 m2; Volumen: 0.00000803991 m3
Proceso por fases - Fase de creación: New
Estructura - Recubrimiento de armadura: Rebar Cover 1 <25 mm>
Name (REC_TCA_M24:REC_TCA_M24:...) | Desfase desde el anfitrión (m)
3799162 | -0.05
3799163 | 3.94934
3799168 | 0.05
3799169 | 4.04934
3825880 | -0.05
3825881 | 3.94934
3825886 | 0.05
3825887 | 4.04934
3825936 | -0.05
3825937 | 3.94934
3825942 | 0.05
3825943 | 4.04934
3825968 | -0.05
3825969 | 3.94934
3825974 | 0.05
3825975 | 4.04934
3839080 | -0.05
3839081 | 3.94934
3839086 | 0.05
3839087 | 4.04934

# IfcFurnishingElement: REC__VRM24165C88EQM:VRM24165C88EQM (10)
In: L0
Type - Material: REC_Acero, S 275JR (Zincado)
Type - Otra - Categoría: Conexiones estructurales; Nombre de familia: REC__VRM24165C88EQM
Type - Restricciones - Elevación por defecto: 13.1234 m
Type - Datos de identidad - Creado por:: DELIPROGAL; Descripción: M24 coupling rod system; Description_ESP: Sistema de varillas de acople M24; Fabricante: RECENSE; Fecha de Creacion:: 11/02/2026; Fecha Ultima Revision:: 23/03/2026; Modelo: DPG_T_M24; Nombre de tipo: VRM24165C88EQM; URL: https://prefabricados.recense.com/prefabricados/fijacion-de-balcones-prefabricados/
Type - Pset_ManufacturerTypeInformation - Manufacturer: RECENSE
Pset_QuantityTakeOff - Reference: VRM24165C88EQM
Otra - Familia: REC__VRM24165C88EQM; Familia y tipo: REC__VRM24165C88EQM: VRM24165C88EQM; ID de tipo: 3934552; Tipo: VRM24165C88EQM
Restricciones - Se mueve con elementos cercanos: no; Anfitrión: Suelo : DPG_Balcon_Prefabricado
Cotas - Área: 0.00667268 m2; Volumen: 0.0000746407 m3
Proceso por fases - Fase de creación: New
Estructura - Recubrimiento de armadura: Rebar Cover 1 <25 mm>
Name (REC__VRM24165C88EQM:VRM24165C88EQM:...) | Desfase desde el anfitrión (m)
3799165 | -0.05
3799171 | 0.05
3825883 | -0.05
3825889 | 0.05
3825939 | -0.05
3825945 | 0.05
3825971 | -0.05
3825977 | 0.05
3839083 | -0.05
3839089 | 0.05

# IfcOpeningElement: Opening (19)
In: L0
Pset_OpeningElementCommon - sets with these values: 2
Name | Depth (m) | Area (m2) | Reference
Suelo:DPG_Balcon_Prefabricado:3592091 | 0.2 | 0.0152013 | Fijacion_de_balcon | Otra - Categoría: Conexiones estructurales; Familia: Fijacion_de_balcon; Familia y tipo: Fijacion_de_balcon: Fijacion_de_balcon; ID de tipo: 3934748; Tipo: Fijacion_de_balcon; Resultados de análisis - DPG_FOR_POS_FORJ: 0.2 m; Restricciones - Anfitrión: Suelo : DPG_Balcon_Prefabricado; Elevación desde el nivel: 0 m; Nivel: L0; Nivel de tabla de planificación: L0; Construcción - DPG_Separador_derecho: no; DPG_Separador_izquierdo: no; Cotas - DPG_POS_FORJADO: 0 m; Proceso por fases - Fase de creación: New; Estructura - Recubrimiento de armadura: Rebar Cover 1 <25 mm>; Otra(Tipo) - Categoría: Conexiones estructurales; Nombre de familia: Fijacion_de_balcon; Restricciones(Tipo) - Elevación por defecto: 0 m; Datos de identidad(Tipo) - Creado por:: DELIPROGAL; Descripción: Bolted connection for precast concrete balconies.; Description_ESP: Conexion atornillada para balcones prefabricados de hormigon; Fabricante: RECENSE; Fecha de Creacion:: 12/02/2026; Fecha Ultima Revision:: 12/02/2026; Modelo: FIJACION DE BALCON; Nombre de tipo: Fijacion_de_balcon; URL: https://prefabricados.recense.com/documentacion/prefabricados/doc/Fijacion_balcones.pdf
4 x Suelo:DPG_Balcon_Prefabricado:3592091 | 0.2 | 0.0152013 | Fijacion_de_balcon | Otra - Categoría: Conexiones estructurales; Familia: Fijacion_de_balcon; Familia y tipo: Fijacion_de_balcon: Fijacion_de_balcon; ID de tipo: 3934748; Tipo: Fijacion_de_balcon; Resultados de análisis - DPG_FOR_POS_FORJ: 0.2 m; Restricciones - Anfitrión: Suelo : DPG_Balcon_Prefabricado; Elevación desde el nivel: 0 m; Construcción - DPG_Separador_derecho: no; DPG_Separador_izquierdo: yes; Cotas - DPG_POS_FORJADO: 0 m; Proceso por fases - Fase de creación: New; Estructura - Recubrimiento de armadura: Rebar Cover 1 <25 mm>; Otra(Tipo) - Categoría: Conexiones estructurales; Nombre de familia: Fijacion_de_balcon; Restricciones(Tipo) - Elevación por defecto: 0 m; Datos de identidad(Tipo) - Creado por:: DELIPROGAL; Descripción: Bolted connection for precast concrete balconies.; Description_ESP: Conexion atornillada para balcones prefabricados de hormigon; Fabricante: RECENSE; Fecha de Creacion:: 12/02/2026; Fecha Ultima Revision:: 12/02/2026; Modelo: FIJACION DE BALCON; Nombre de tipo: Fijacion_de_balcon; URL: https://prefabricados.recense.com/documentacion/prefabricados/doc/Fijacion_balcones.pdf
Suelo:DPG_Losa Principal Obra:3787192 | 0.2 | 0.0152013 | Fijacion_de_balcon | Otra - Categoría: Conexiones estructurales; Familia: Fijacion_de_balcon; Familia y tipo: Fijacion_de_balcon: Fijacion_de_balcon; ID de tipo: 3934748; Tipo: Fijacion_de_balcon; Resultados de análisis - DPG_FOR_POS_FORJ: 0.2 m; Restricciones - Anfitrión: Suelo : DPG_Balcon_Prefabricado; Elevación desde el nivel: 0 m; Nivel: L0; Nivel de tabla de planificación: L0; Construcción - DPG_Separador_derecho: no; DPG_Separador_izquierdo: no; Cotas - DPG_POS_FORJADO: 0 m; Proceso por fases - Fase de creación: New; Estructura - Recubrimiento de armadura: Rebar Cover 1 <25 mm>; Otra(Tipo) - Categoría: Conexiones estructurales; Nombre de familia: Fijacion_de_balcon; Restricciones(Tipo) - Elevación por defecto: 0 m; Datos de identidad(Tipo) - Creado por:: DELIPROGAL; Descripción: Bolted connection for precast concrete balconies.; Description_ESP: Conexion atornillada para balcones prefabricados de hormigon; Fabricante: RECENSE; Fecha de Creacion:: 12/02/2026; Fecha Ultima Revision:: 12/02/2026; Modelo: FIJACION DE BALCON; Nombre de tipo: Fijacion_de_balcon; URL: https://prefabricados.recense.com/documentacion/prefabricados/doc/Fijacion_balcones.pdf
Suelo:DPG_Losa Principal Obra:3787192 |  |  | Fijacion_de_balcon | Otra - Categoría: Conexiones estructurales; Familia: Fijacion_de_balcon; Familia y tipo: Fijacion_de_balcon: Fijacion_de_balcon; ID de tipo: 3934748; Tipo: Fijacion_de_balcon; Resultados de análisis - DPG_FOR_POS_FORJ: 0.2 m; Restricciones - Anfitrión: Suelo : DPG_Balcon_Prefabricado; Elevación desde el nivel: 0 m; Nivel: L0; Nivel de tabla de planificación: L0; Construcción - DPG_Separador_derecho: no; DPG_Separador_izquierdo: no; Cotas - DPG_POS_FORJADO: 0 m; Proceso por fases - Fase de creación: New; Estructura - Recubrimiento de armadura: Rebar Cover 1 <25 mm>; Otra(Tipo) - Categoría: Conexiones estructurales; Nombre de familia: Fijacion_de_balcon; Restricciones(Tipo) - Elevación por defecto: 0 m; Datos de identidad(Tipo) - Creado por:: DELIPROGAL; Descripción: Bolted connection for precast concrete balconies.; Description_ESP: Conexion atornillada para balcones prefabricados de hormigon; Fabricante: RECENSE; Fecha de Creacion:: 12/02/2026; Fecha Ultima Revision:: 12/02/2026; Modelo: FIJACION DE BALCON; Nombre de tipo: Fijacion_de_balcon; URL: https://prefabricados.recense.com/documentacion/prefabricados/doc/Fijacion_balcones.pdf
REC-PAA150708T14:PAA150708T14:3863579:1 | 0.05 | 0.00166851 | PAA150708T14
REC-PAA150708T14:PAA150708T14:3863579:2 | 0.05 | 0.00166851 | PAA150708T14
REC-PAA150708T14:PAA150708T14:3863579:3 | 0.05 | 0.00166851 | PAA150708T14
REC-PAA150708T14:PAA150708T14:3863579:4 | 0.05 | 0.00166851 | PAA150708T14
REC-PAA150708T14:PAA150708T14:3884089:1 | 0.05 | 0.00166851 | PAA150708T14
REC-PAA150708T14:PAA150708T14:3884089:2 | 0.05 | 0.00166851 | PAA150708T14
REC-PAA150708T14:PAA150708T14:3884089:3 | 0.05 | 0.00166851 | PAA150708T14
REC-PAA150708T14:PAA150708T14:3884089:4 | 0.05 | 0.00166851 | PAA150708T14
REC-PAA150708T14:PAA150708T14:3884164:1 | 0.05 | 0.00166851 | PAA150708T14
REC-PAA150708T14:PAA150708T14:3884164:2 | 0.05 | 0.00166851 | PAA150708T14
REC-PAA150708T14:PAA150708T14:3884164:3 | 0.05 | 0.00166851 | PAA150708T14
REC-PAA150708T14:PAA150708T14:3884164:4 | 0.05 | 0.00166851 | PAA150708T14

# IfcSlab: Suelo:DPG_Aislamiento Suelo, Suelo:DPG_Aislamiento Suelo:3841536
In: L0
Type - PredefinedType: FLOOR; Material: Lana de roca 0.04 m
Type - Otra - Categoría: Suelos; Nombre de familia: Suelo
Type - Construcción - Función: Interior; Grosor predeterminado: 0.04 m
Type - Gráficos - Color de relleno de detalle bajo: 0
Type - Datos de identidad - Nombre de tipo: DPG_Aislamiento Suelo
Type - Materiales y acabados - Material estructural: Lana de roca
Type - Propiedades analíticas - Absortancia: 0.7; Aspereza: 3; Coeficiente de transferencia de calor (U): 0.85 kg/K/s3; Masa térmica: 5680 kg/K/s2; Resistencia térmica (R): 1.17647 s3*K/kg
Type - Pset_SlabCommon - ThermalTransmittance: 0.85 kg/K/s3
Pset_QuantityTakeOff - Reference: DPG_Aislamiento Suelo; sets with these values: 2
Pset_SlabCommon - IsExternal: no; LoadBearing: no; PitchAngle: 0 deg; Reference: DPG_Aislamiento Suelo
BaseQuantities - Width: 2.2 m; Perimeter: 8.26 m; GrossArea: 4.246 m2; NetArea: 4.246 m2; GrossVolume: 0.16984 m3; NetVolume: 0.16984 m3
Otra - Familia: Suelo; Familia y tipo: Suelo: DPG_Aislamiento Suelo; ID de tipo: 3841562; Tipo: DPG_Aislamiento Suelo
Restricciones - Nivel: L0; Delimitación de habitación: yes; Relacionado con masa: no; Desfase de altura desde nivel: 0.04 m
Cotas - Elevación en parte inferior: 0 m; Elevación en parte inferior de núcleo: 0 m; Área: 4.246 m2; Elevación en parte superior: 0.04 m; Elevación en parte superior de núcleo: 0.04 m; Grosor: 0.04 m; Perímetro: 8.26 m; Volumen: 0.16984 m3
Datos de identidad - Tiene asociación: no
Proceso por fases - Fase de creación: New
Estructura - Estructura: no

# IfcSlab: Suelo:DPG_Balcon_Prefabricado, Suelo:DPG_Balcon_Prefabricado:3592091
In: L0
Type - PredefinedType: FLOOR; Material: Hormigón reforzado con fibra de vidrio 0.2 m
Type - Otra - Categoría: Suelos; Nombre de familia: Suelo
Type - Construcción - Función: Interior; Grosor predeterminado: 0.2 m
Type - Gráficos - Color de relleno de detalle bajo: 0
Type - Datos de identidad - Nombre de tipo: DPG_Balcon_Prefabricado
Type - Materiales y acabados - Material estructural: Hormigón reforzado con fibra de vidrio
Type - Propiedades analíticas - Absortancia: 0.7; Aspereza: 3; Coeficiente de transferencia de calor (U): 5.23 kg/K/s3; Masa térmica: 302220 kg/K/s2; Resistencia térmica (R): 0.191205 s3*K/kg
Type - Pset_SlabCommon - ThermalTransmittance: 5.23 kg/K/s3
Pset_QuantityTakeOff - Reference: DPG_Balcon_Prefabricado; sets with these values: 2
Pset_SlabCommon - Reference: DPG_Balcon_Prefabricado; IsExternal: no; LoadBearing: no; PitchAngle: 0 deg
BaseQuantities - Perimeter: 10.4042 m; GrossArea: 5.96157 m2; NetArea: 5.96157 m2; GrossVolume: 1.19231 m3; NetVolume: 1.19231 m3
Otra - Familia: Suelo; Familia y tipo: Suelo: DPG_Balcon_Prefabricado; ID de tipo: 3799245; Tipo: DPG_Balcon_Prefabricado
Restricciones - Nivel: L0; Delimitación de habitación: yes; Desfase de altura desde nivel: 0 m; Relacionado con masa: no
Cotas - Área: 5.96157 m2; Elevación en parte inferior: -0.2 m; Elevación en parte inferior de núcleo: -0.2 m; Elevación en parte superior: 0 m; Elevación en parte superior de núcleo: 0 m; Grosor: 0.2 m; Perímetro: 9.88416 m; Volumen: 1.19231 m3
Datos de identidad - Tiene asociación: no
Proceso por fases - Fase de creación: New
Estructura - Estructura: no

# IfcSlab: Suelo:DPG_Ceramica (2)
In: L0
Type - PredefinedType: FLOOR; Material: Azulejo, porcelana, 6 pulg. 0.01 m
Type - Otra - Categoría: Suelos; Nombre de familia: Suelo
Type - Construcción - Función: Interior; Grosor predeterminado: 0.01 m
Type - Gráficos - Color de relleno de detalle bajo: 0
Type - Datos de identidad - Nombre de tipo: DPG_Ceramica
Type - Materiales y acabados - Material estructural: Azulejo, porcelana, 6 pulg.
Type - Propiedades analíticas - Absortancia: 0.7; Aspereza: 3; Coeficiente de transferencia de calor (U): 120 kg/K/s3; Masa térmica: 17000 kg/K/s2; Resistencia térmica (R): 0.00833333 s3*K/kg
Type - Pset_SlabCommon - ThermalTransmittance: 120 kg/K/s3
Pset_QuantityTakeOff - Reference: DPG_Ceramica; sets with these values: 2
Pset_SlabCommon - IsExternal: no; LoadBearing: no; PitchAngle: 0 deg; Reference: DPG_Ceramica
Otra - Familia: Suelo; Familia y tipo: Suelo: DPG_Ceramica; ID de tipo: 3607552; Tipo: DPG_Ceramica
Restricciones - Nivel: L0; Delimitación de habitación: yes; Relacionado con masa: no
Cotas - Grosor: 0.01 m
Datos de identidad - Tiene asociación: no
Proceso por fases - Fase de creación: New
Estructura - Estructura: no
Name (Suelo:DPG_Ceramica:...) | GrossArea (m2) = NetArea (m2) = Área (m2) | NetVolume (m3) | Desfase de altura desde nivel (m) | Perímetro (m) | Volumen (m3)
3743870 | 2.14262 | 0.021424 | 0.125 | 6.2 | 0.0214262 | Material: Azulejo, porcelana, 6 pulg.; Edición de forma de losa - Condición de borde curvado: 0
3841554 | 3.6284 | 0.036284 | 0.11 | 82.021 | 0.036284 | BaseQuantities - Width: 1.88 m; Perimeter: 7.62 m; GrossVolume: 0.036284 m3; Cotas - Elevación en parte inferior: 0.1 m; Elevación en parte inferior de núcleo: 0.1 m; Elevación en parte superior: 0.11 m; Elevación en parte superior de núcleo: 0.11 m

# IfcSlab: Suelo:DPG_Lamina, Suelo:DPG_Lamina:3878087
In: L0
Type - PredefinedType: FLOOR
Type - Otra - Categoría: Suelos; Nombre de familia: Suelo
Type - Construcción - Función: Interior; Grosor predeterminado: 0.005 m
Type - Gráficos - Color de relleno de detalle bajo: 0
Type - Datos de identidad - Nombre de tipo: DPG_Lamina
Type - Materiales y acabados - Material estructural: Caucho, butilo
Type - Propiedades analíticas - Absortancia: 0.7; Aspereza: 3; Coeficiente de transferencia de calor (U): 17.6 kg/K/s3; Masa térmica: 8847 kg/K/s2; Resistencia térmica (R): 0.0568182 s3*K/kg
Type - Pset_SlabCommon - ThermalTransmittance: 17.6 kg/K/s3
Material: Caucho, butilo
Pset_QuantityTakeOff - Reference: DPG_Lamina; sets with these values: 2
Pset_SlabCommon - IsExternal: no; LoadBearing: no; Reference: DPG_Lamina; PitchAngle: 1.47786 deg
BaseQuantities - GrossArea: 2.59589 m2; NetArea: 2.59589 m2; NetVolume: 0.012978 m3
Otra - Familia: Suelo; Familia y tipo: Suelo: DPG_Lamina; ID de tipo: 3878100; Tipo: DPG_Lamina
Restricciones - Nivel: L0; Delimitación de habitación: yes; Relacionado con masa: no; Desfase de altura desde nivel: 0.105 m
Cotas - Área: 2.59589 m2; Grosor: 0.005 m; Perímetro: 6.64 m; Volumen: 0.0129794 m3
Datos de identidad - Tiene asociación: no
Proceso por fases - Fase de creación: New
Edición de forma de losa - Condición de borde curvado: 0
Estructura - Estructura: no

# IfcSlab: Suelo:DPG_Losa Principal Obra, Suelo:DPG_Losa Principal Obra:3787192
In: L0
Type - PredefinedType: FLOOR; Material: DPG_Losa Principal Obra 0.3 m
Type - Otra - Categoría: Suelos; Nombre de familia: Suelo
Type - Construcción - Función: Interior; Grosor predeterminado: 0.3 m
Type - Gráficos - Color de relleno de detalle bajo: 0
Type - Datos de identidad - Nombre de tipo: DPG_Losa Principal Obra
Type - Materiales y acabados - Material estructural: DPG_Losa Principal Obra
Type - Propiedades analíticas - Absortancia: 0.7; Aspereza: 3
Pset_QuantityTakeOff - Reference: DPG_Losa Principal Obra; sets with these values: 2
Pset_SlabCommon - IsExternal: no; LoadBearing: no; PitchAngle: 0 deg; Reference: DPG_Losa Principal Obra
BaseQuantities - Perimeter: 11.1642 m; GrossArea: 7.16416 m2; NetArea: 7.16416 m2; GrossVolume: 2.14925 m3; NetVolume: 2.14913 m3
Otra - Familia: Suelo; Familia y tipo: Suelo: DPG_Losa Principal Obra; ID de tipo: 759; Tipo: DPG_Losa Principal Obra
Restricciones - Nivel: L0; Delimitación de habitación: yes; Desfase de altura desde nivel: 0 m; Relacionado con masa: no
Cotas - Elevación en parte superior: 0 m; Elevación en parte superior de núcleo: 0 m; Área: 7.16416 m2; Elevación en parte inferior: -0.3 m; Elevación en parte inferior de núcleo: -0.3 m; Grosor: 0.3 m; Perímetro: 11.1642 m; Volumen: 2.14913 m3
Datos de identidad - Tiene asociación: no
Proceso por fases - Fase de creación: New
Estructura - Estructura: no

# IfcSlab: Suelo:DPG_Pegamento cemento (2)
In: L0
Type - PredefinedType: FLOOR; Material: Hormigón - Hormigón moldeado in situ 0.01 m
Type - Otra - Categoría: Suelos; Nombre de familia: Suelo
Type - Construcción - Función: Interior; Grosor predeterminado: 0.01 m
Type - Gráficos - Color de relleno de detalle bajo: 0
Type - Datos de identidad - Nombre de tipo: DPG_Pegamento cemento
Type - Materiales y acabados - Material estructural: Hormigón - Hormigón moldeado in situ
Type - Propiedades analíticas - Absortancia: 0.7; Aspereza: 3
Pset_QuantityTakeOff - Reference: DPG_Pegamento cemento; sets with these values: 2
Pset_SlabCommon - IsExternal: no; LoadBearing: no; Reference: DPG_Pegamento cemento
Otra - Familia: Suelo; Familia y tipo: Suelo: DPG_Pegamento cemento; ID de tipo: 3607442; Tipo: DPG_Pegamento cemento
Restricciones - Nivel: L0; Delimitación de habitación: yes; Relacionado con masa: no
Cotas - Grosor: 0.01 m
Datos de identidad - Tiene asociación: no
Proceso por fases - Fase de creación: New
Estructura - Estructura: no
Name (Suelo:DPG_Pegamento cemento:...) | PitchAngle (deg) | GrossArea (m2) = NetArea (m2) = Área (m2) | NetVolume (m3) | Desfase de altura desde nivel (m) | Perímetro (m) | Volumen (m3)
3743797 | 1.45001 | 2.39566 | 0.023954 | 0.115 | 6.45 | 0.0239566 | Material: Hormigón - Hormigón moldeado in situ; Edición de forma de losa - Condición de borde curvado: 0
3841548 | 0 | 3.86 | 0.0386 | 0.1 | 7.86 | 0.0386 | BaseQuantities - Width: 2 m; Perimeter: 7.86 m; GrossVolume: 0.0386 m3; Cotas - Elevación en parte inferior: 0.09 m; Elevación en parte inferior de núcleo: 0.09 m; Elevación en parte superior: 0.1 m; Elevación en parte superior de núcleo: 0.1 m

# IfcSlab: Suelo:DPG_Recrecido, Suelo:DPG_Recrecido:3607293
In: L0
Type - PredefinedType: FLOOR
Type - Otra - Categoría: Suelos; Nombre de familia: Suelo
Type - Construcción - Función: Interior; Grosor predeterminado: 0.1 m
Type - Gráficos - Color de relleno de detalle bajo: 0
Type - Datos de identidad - Nombre de tipo: DPG_Recrecido
Type - Materiales y acabados - Material estructural: Hormigón, ligero
Type - Propiedades analíticas - Absortancia: 0.7; Aspereza: 3; Coeficiente de transferencia de calor (U): 2.09 kg/K/s3; Masa térmica: 62415 kg/K/s2; Resistencia térmica (R): 0.478469 s3*K/kg
Type - Pset_SlabCommon - ThermalTransmittance: 2.09 kg/K/s3
Material: Hormigón, ligero
Pset_QuantityTakeOff - Reference: DPG_Recrecido; sets with these values: 2
Pset_SlabCommon - IsExternal: no; LoadBearing: no; Reference: DPG_Recrecido; PitchAngle: 1.51977 deg
BaseQuantities - GrossArea: 2.82913 m2; NetArea: 2.82913 m2; NetVolume: 0.261523 m3
Otra - Familia: Suelo; Familia y tipo: Suelo: DPG_Recrecido; ID de tipo: 3607308; Tipo: DPG_Recrecido
Restricciones - Nivel: L0; Delimitación de habitación: yes; Relacionado con masa: no; Desfase de altura desde nivel: 0.1 m
Cotas - Área: 2.82913 m2; Elevación en parte inferior: 0 m; Elevación en parte inferior de núcleo: 0 m; Perímetro: 6.88 m; Volumen: 0.261523 m3
Datos de identidad - Tiene asociación: no
Proceso por fases - Fase de creación: New
Edición de forma de losa - Condición de borde curvado: 0
Estructura - Estructura: no

# IfcSlab: Suelo:DPG_Recrecido INT, Suelo:DPG_Recrecido INT:3841542
In: L0
Type - PredefinedType: FLOOR; Material: Hormigón, ligero 0.05 m
Type - Otra - Categoría: Suelos; Nombre de familia: Suelo
Type - Construcción - Función: Interior; Grosor predeterminado: 0.05 m
Type - Gráficos - Color de relleno de detalle bajo: 0
Type - Datos de identidad - Nombre de tipo: DPG_Recrecido INT
Type - Materiales y acabados - Material estructural: Hormigón, ligero
Type - Propiedades analíticas - Absortancia: 0.7; Aspereza: 3; Coeficiente de transferencia de calor (U): 4.18 kg/K/s3; Masa térmica: 31207.5 kg/K/s2; Resistencia térmica (R): 0.239234 s3*K/kg
Type - Pset_SlabCommon - ThermalTransmittance: 4.18 kg/K/s3
Pset_QuantityTakeOff - Reference: DPG_Recrecido INT; sets with these values: 2
Pset_SlabCommon - IsExternal: no; LoadBearing: no; PitchAngle: 0 deg; Reference: DPG_Recrecido INT
BaseQuantities - Width: 2.1 m; Perimeter: 8.06 m; GrossArea: 4.053 m2; NetArea: 4.053 m2; GrossVolume: 0.20265 m3; NetVolume: 0.20265 m3
Otra - Familia: Suelo; Familia y tipo: Suelo: DPG_Recrecido INT; ID de tipo: 3841675; Tipo: DPG_Recrecido INT
Restricciones - Nivel: L0; Delimitación de habitación: yes; Relacionado con masa: no; Desfase de altura desde nivel: 0.09 m
Cotas - Área: 4.053 m2; Elevación en parte inferior: 0.04 m; Elevación en parte inferior de núcleo: 0.04 m; Elevación en parte superior: 0.09 m; Grosor: 0.05 m; Perímetro: 8.06 m; Volumen: 0.20265 m3
Datos de identidad - Tiene asociación: no
Proceso por fases - Fase de creación: New
Estructura - Estructura: no

# IfcWall: Muro básico:DPG_Aislamiento 2, Muro básico:DPG_Aislamiento 2:3840662
In: L0
Type - PredefinedType: STANDARD; Material: Lana de roca TRANS 0.1 m
Type - Otra - Categoría: Muros; Nombre de familia: Muro básico
Type - Construcción - Envolvente en extremos: Ninguno; Envolvente en inserciones: Sin envolvente; Función: Retención; Anchura: 0.1 m
Type - Gráficos - Color de relleno de detalle bajo: 0
Type - Datos de identidad - Nombre de tipo: DPG_Aislamiento 2
Type - Propiedades analíticas - Absortancia: 0.7; Aspereza: 3; Coeficiente de transferencia de calor (U): 0.34 kg/K/s3; Masa térmica: 14200 kg/K/s2; Resistencia térmica (R): 2.94118 s3*K/kg
Type - Pset_WallCommon - ThermalTransmittance: 0.34 kg/K/s3
Pset_QuantityTakeOff - Reference: DPG_Aislamiento 2; sets with these values: 2
Pset_WallCommon - LoadBearing: no; IsExternal: yes; ExtendToStructure: no; Reference: DPG_Aislamiento 2
BaseQuantities - Length: 2.74208 m; NetVolume: 0.0493268 m3
Otra - Familia: Muro básico; Familia y tipo: Muro básico: DPG_Aislamiento 2; ID de tipo: 3908844; Tipo: DPG_Aislamiento 2
Restricciones - Relacionado con masa: no; Delimitación de habitación: no; Desfase superior: 0 m; Distancia de extensión de base: 0 m; Distancia de extensión superior: 0 m; La base está enlazada: no; La parte superior está enlazada: no; Línea de ubicación: Cara de acabado: Exterior; Restricción de base: L0; Altura desconectada: 0.2 m; Desfase de base: -0.2 m
Cotas - Área: 0.534574 m2; Longitud: 2.74208 m; Volumen: 0.0493268 m3
Proceso por fases - Fase de creación: New
Estructura - Estructura: no; Uso estructural: No portante
Definición de sección transversal - Sección transversal: Vertical

# IfcWall: Muro básico:DPG_Pegamento cementoso, Muro básico:DPG_Pegamento cementoso:3889761
In: L0
Type - PredefinedType: STANDARD; Material: Hormigón - Hormigón moldeado in situ 0.01 m
Type - Otra - Categoría: Muros; Nombre de familia: Muro básico
Type - Construcción - Envolvente en extremos: Ninguno; Envolvente en inserciones: Sin envolvente; Función: Retención; Anchura: 0.01 m
Type - Gráficos - Color de relleno de detalle bajo: 0
Type - Datos de identidad - Nombre de tipo: DPG_Pegamento cementoso
Type - Propiedades analíticas - Absortancia: 0.7; Aspereza: 3
Pset_QuantityTakeOff - Reference: DPG_Pegamento cementoso; sets with these values: 2
Pset_WallCommon - LoadBearing: no; IsExternal: yes; ExtendToStructure: no; Reference: DPG_Pegamento cementoso
BaseQuantities - Length: 1.165 m; NetVolume: 0.00149282 m3
Otra - Familia: Muro básico; Familia y tipo: Muro básico: DPG_Pegamento cementoso; ID de tipo: 3863834; Tipo: DPG_Pegamento cementoso
Restricciones - Relacionado con masa: no; Delimitación de habitación: no; Desfase superior: 0 m; Distancia de extensión de base: 0 m; Distancia de extensión superior: 0 m; La base está enlazada: no; La parte superior está enlazada: no; Línea de ubicación: Cara de acabado: Exterior; Restricción de base: L0; Altura desconectada: 0.0912673 m; Desfase de base: 0.108733 m
Cotas - Área: 0.149906 m2; Longitud: 1.165 m; Volumen: 0.00149282 m3
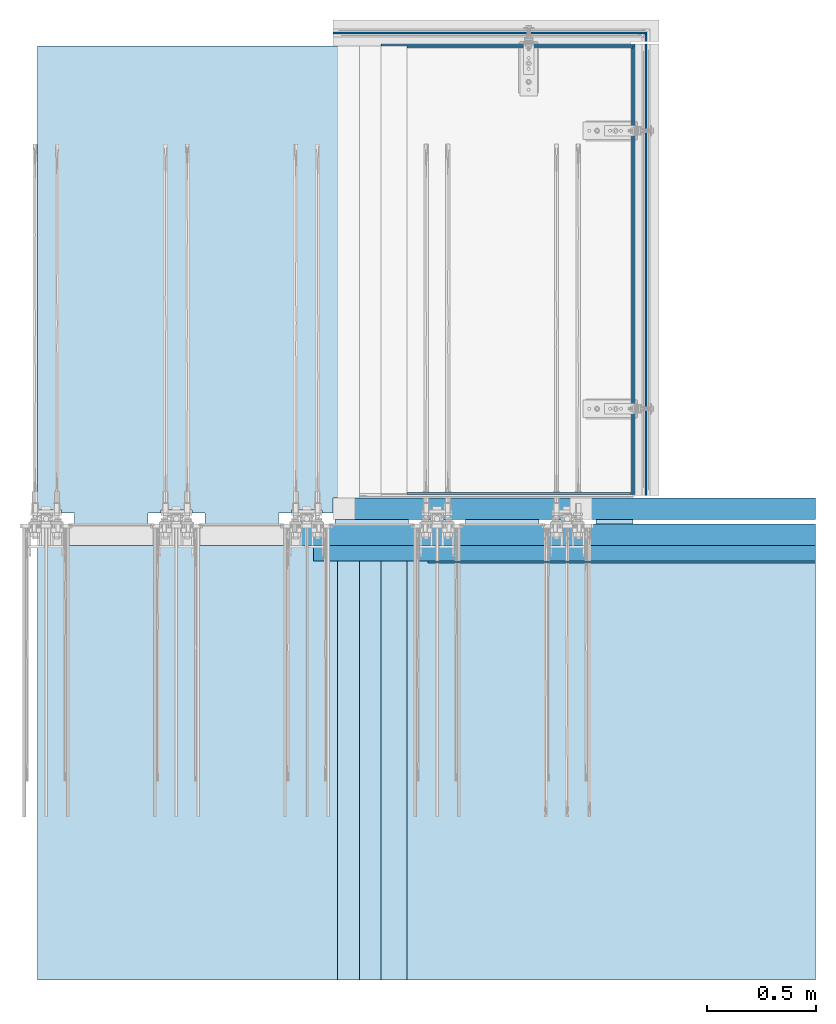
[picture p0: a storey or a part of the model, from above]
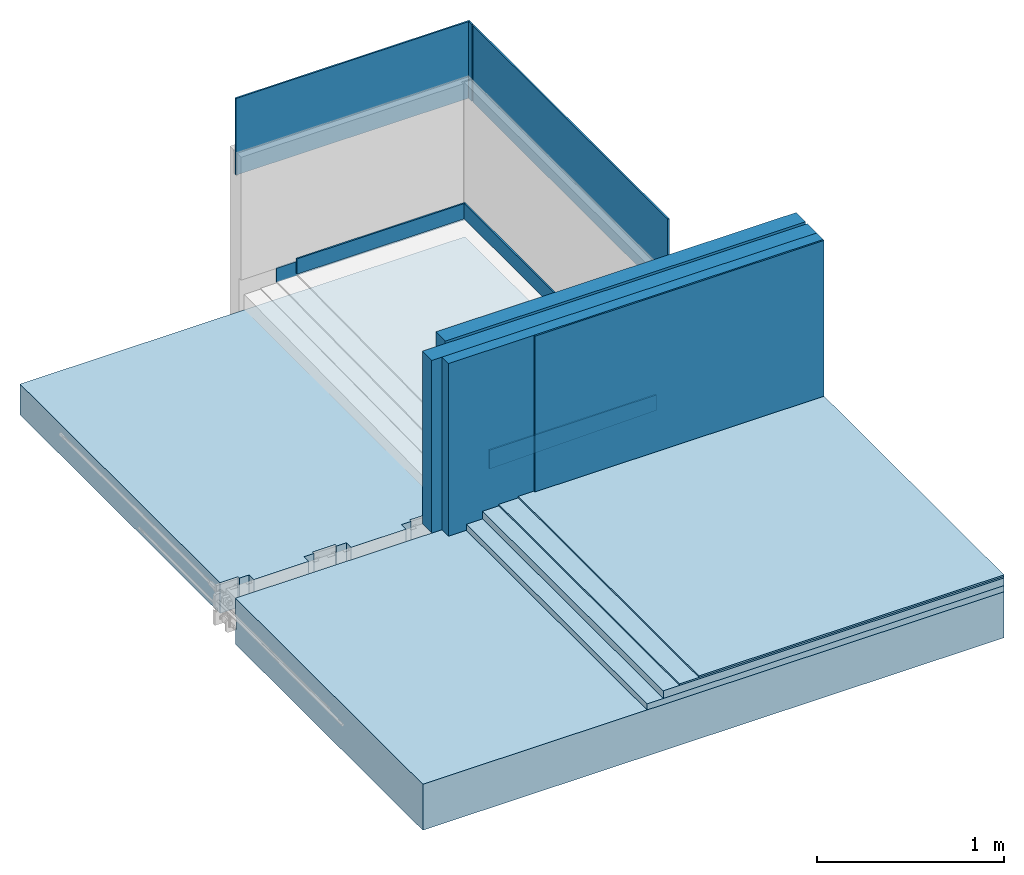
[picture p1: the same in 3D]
Properties of the parts of a building model (IFC2X3), part 2 of 2

# IfcWall: Muro básico:DPG_Pegamento cementoso, Muro básico:DPG_Pegamento cementoso:3889761
Proceso por fases - Fase de creación: New
Estructura - Estructura: no; Uso estructural: No portante
Definición de sección transversal - Sección transversal: Vertical

# IfcWallStandardCase: Muro básico:DPG_Aislamiento, Muro básico:DPG_Aislamiento:3839128
In: L0
Type - PredefinedType: STANDARD; Material: Lana de roca 0.1 m
Type - Otra - Categoría: Muros; Nombre de familia: Muro básico
Type - Construcción - Anchura: 0.1 m; Envolvente en extremos: Ninguno; Envolvente en inserciones: Sin envolvente; Función: Retención
Type - Gráficos - Color de relleno de detalle bajo: 0
Type - Datos de identidad - Nombre de tipo: DPG_Aislamiento
Type - Propiedades analíticas - Absortancia: 0.7; Aspereza: 3; Coeficiente de transferencia de calor (U): 0.34 kg/K/s3; Masa térmica: 14200 kg/K/s2; Resistencia térmica (R): 2.94118 s3*K/kg
Type - Pset_WallCommon - ThermalTransmittance: 0.34 kg/K/s3
BaseQuantities - Height: 1.125 m; Length: 2.3725 m; Width: 0.1 m; GrossFootprintArea: 0.23725 m2; GrossVolume: 0.266906 m3; GrossSideArea: 2.66906 m2; NetSideArea: 2.66906 m2; NetVolume: 0.266906 m3
Pset_QuantityTakeOff - Reference: DPG_Aislamiento; sets with these values: 2
Pset_WallCommon - LoadBearing: no; Reference: DPG_Aislamiento; IsExternal: yes; ExtendToStructure: no
Otra - Familia: Muro básico; Familia y tipo: Muro básico: DPG_Aislamiento; ID de tipo: 3839131; Tipo: DPG_Aislamiento
Restricciones - Relacionado con masa: no; Altura desconectada: 1.125 m; Delimitación de habitación: no; Desfase de base: 0 m; Desfase superior: 0 m; Distancia de extensión de base: 0 m; Distancia de extensión superior: 0 m; La base está enlazada: no; La parte superior está enlazada: no; Línea de ubicación: Cara de acabado: Exterior; Restricción de base: L0
Cotas - Área: 2.66906 m2; Longitud: 2.3725 m; Volumen: 0.266906 m3
Proceso por fases - Fase de creación: New
Estructura - Estructura: no; Uso estructural: No portante
Definición de sección transversal - Sección transversal: Vertical

# IfcWallStandardCase: Muro básico:DPG_Enlucido, Muro básico:DPG_Enlucido:3839130
In: L0
Type - PredefinedType: STANDARD; Material: Enlucido 0.01 m
Type - Otra - Categoría: Muros; Nombre de familia: Muro básico
Type - Construcción - Envolvente en extremos: Ninguno; Envolvente en inserciones: Sin envolvente; Función: Retención; Anchura: 0.01 m
Type - Gráficos - Color de relleno de detalle bajo: 0
Type - Datos de identidad - Nombre de tipo: DPG_Enlucido
Type - Propiedades analíticas - Absortancia: 0.7; Aspereza: 3; Coeficiente de transferencia de calor (U): 51 kg/K/s3; Masa térmica: 10752 kg/K/s2; Resistencia térmica (R): 0.0196078 s3*K/kg
Type - Pset_WallCommon - ThermalTransmittance: 51 kg/K/s3
BaseQuantities - Height: 1.015 m; Length: 1.7825 m; Width: 0.01 m; GrossFootprintArea: 0.017825 m2; GrossVolume: 0.0180923 m3; GrossSideArea: 1.80923 m2; NetSideArea: 1.80923 m2; NetVolume: 0.0180923 m3
Pset_QuantityTakeOff - Reference: DPG_Enlucido; sets with these values: 2
Pset_WallCommon - LoadBearing: no; IsExternal: yes; ExtendToStructure: no; Reference: DPG_Enlucido
Otra - Familia: Muro básico; Familia y tipo: Muro básico: DPG_Enlucido; ID de tipo: 3839135; Tipo: DPG_Enlucido
Restricciones - Relacionado con masa: no; Delimitación de habitación: no; Desfase superior: 0 m; Distancia de extensión de base: 0 m; Distancia de extensión superior: 0 m; La base está enlazada: no; La parte superior está enlazada: no; Línea de ubicación: Cara de acabado: Exterior; Restricción de base: L0; Altura desconectada: 1.015 m; Desfase de base: 0.11 m
Cotas - Área: 1.80923 m2; Longitud: 1.7825 m; Volumen: 0.0180923 m3
Proceso por fases - Fase de creación: New
Estructura - Estructura: no; Uso estructural: No portante
Definición de sección transversal - Sección transversal: Vertical

# IfcWallStandardCase: Muro básico:DPG_Ladrillo, Muro básico:DPG_Ladrillo:3839129
In: L0
Type - PredefinedType: STANDARD; Material: Ladrillo, común, marrón 0.07 m
Type - Otra - Categoría: Muros; Nombre de familia: Muro básico
Type - Construcción - Envolvente en extremos: Ninguno; Envolvente en inserciones: Sin envolvente; Función: Retención; Anchura: 0.07 m
Type - Gráficos - Color de relleno de detalle bajo: 0
Type - Datos de identidad - Nombre de tipo: DPG_Ladrillo
Type - Propiedades analíticas - Absortancia: 0.7; Aspereza: 3; Coeficiente de transferencia de calor (U): 7.71429 kg/K/s3; Masa térmica: 91140 kg/K/s2; Resistencia térmica (R): 0.12963 s3*K/kg
Type - Pset_WallCommon - ThermalTransmittance: 7.71429 kg/K/s3
BaseQuantities - Height: 1.125 m; Length: 2.31 m; Width: 0.07 m; GrossFootprintArea: 0.1617 m2; GrossVolume: 0.181913 m3; GrossSideArea: 2.59875 m2; NetSideArea: 2.59875 m2; NetVolume: 0.181912 m3
Pset_QuantityTakeOff - Reference: DPG_Ladrillo; sets with these values: 2
Pset_WallCommon - LoadBearing: no; IsExternal: yes; ExtendToStructure: no; Reference: DPG_Ladrillo
Otra - Familia: Muro básico; Familia y tipo: Muro básico: DPG_Ladrillo; ID de tipo: 3839133; Tipo: DPG_Ladrillo
Restricciones - Relacionado con masa: no; Delimitación de habitación: no; Desfase de base: 0 m; Desfase superior: 0 m; Distancia de extensión de base: 0 m; Distancia de extensión superior: 0 m; La base está enlazada: no; La parte superior está enlazada: no; Línea de ubicación: Cara de acabado: Exterior; Restricción de base: L0; Altura desconectada: 1.125 m
Cotas - Área: 2.59875 m2; Longitud: 2.31 m; Volumen: 0.181912 m3
Proceso por fases - Fase de creación: New
Estructura - Estructura: no; Uso estructural: No portante
Definición de sección transversal - Sección transversal: Vertical

# IfcWallStandardCase: Muro básico:DPG_Panel_Pref, Muro básico:DPG_Panel_Pref:3840355
In: L0
Type - PredefinedType: STANDARD; Material: Hormigón panel 0.1 m
Type - Otra - Categoría: Muros; Nombre de familia: Muro básico
Type - Construcción - Envolvente en extremos: Ninguno; Envolvente en inserciones: Sin envolvente; Función: Retención; Anchura: 0.1 m
Type - Gráficos - Color de relleno de detalle bajo: 0
Type - Datos de identidad - Nombre de tipo: DPG_Panel_Pref
Type - Propiedades analíticas - Absortancia: 0.7; Aspereza: 3; Coeficiente de transferencia de calor (U): 10.46 kg/K/s3; Masa térmica: 151110 kg/K/s2; Resistencia térmica (R): 0.0956023 s3*K/kg
Type - Pset_WallCommon - ThermalTransmittance: 10.46 kg/K/s3
BaseQuantities - Height: 1.105 m; Length: 2.22 m; Width: 0.1 m; GrossFootprintArea: 0.222 m2; GrossVolume: 0.24531 m3; GrossSideArea: 2.4531 m2; NetSideArea: 2.4531 m2; NetVolume: 0.24531 m3
Pset_QuantityTakeOff - Reference: DPG_Panel_Pref; sets with these values: 2
Pset_WallCommon - LoadBearing: no; IsExternal: yes; ExtendToStructure: no; Reference: DPG_Panel_Pref
Otra - Familia: Muro básico; Familia y tipo: Muro básico: DPG_Panel_Pref; ID de tipo: 3840483; Tipo: DPG_Panel_Pref
Restricciones - Relacionado con masa: no; Delimitación de habitación: no; Desfase superior: 0 m; Distancia de extensión de base: 0 m; Distancia de extensión superior: 0 m; La base está enlazada: no; La parte superior está enlazada: no; Línea de ubicación: Cara de acabado: Exterior; Restricción de base: L0; Altura desconectada: 1.105 m; Desfase de base: 0.02 m
Cotas - Área: 2.4531 m2; Longitud: 2.22 m; Volumen: 0.24531 m3
Proceso por fases - Fase de creación: New
Estructura - Estructura: no; Uso estructural: No portante
Definición de sección transversal - Sección transversal: Vertical

# IfcWallStandardCase: Muro básico:DPG_Pegamento cementoso (2)
In: L0
Type - PredefinedType: STANDARD; Material: Hormigón - Hormigón moldeado in situ 0.01 m
Type - Otra - Categoría: Muros; Nombre de familia: Muro básico
Type - Construcción - Envolvente en extremos: Ninguno; Envolvente en inserciones: Sin envolvente; Función: Retención; Anchura: 0.01 m
Type - Gráficos - Color de relleno de detalle bajo: 0
Type - Datos de identidad - Nombre de tipo: DPG_Pegamento cementoso
Type - Propiedades analíticas - Absortancia: 0.7; Aspereza: 3
BaseQuantities - Height: 0.0912673 m; Width: 0.01 m
Pset_QuantityTakeOff - Reference: DPG_Pegamento cementoso; sets with these values: 2
Pset_WallCommon - LoadBearing: no; IsExternal: yes; ExtendToStructure: no; Reference: DPG_Pegamento cementoso
Otra - Familia: Muro básico; Familia y tipo: Muro básico: DPG_Pegamento cementoso; ID de tipo: 3863834; Tipo: DPG_Pegamento cementoso
Restricciones - Relacionado con masa: no; Delimitación de habitación: no; Desfase superior: 0 m; Distancia de extensión de base: 0 m; Distancia de extensión superior: 0 m; La base está enlazada: no; La parte superior está enlazada: no; Línea de ubicación: Cara de acabado: Exterior; Restricción de base: L0; Altura desconectada: 0.0912673 m; Desfase de base: 0.108733 m
Proceso por fases - Fase de creación: New
Estructura - Estructura: no; Uso estructural: No portante
Definición de sección transversal - Sección transversal: Vertical
Name (Muro básico:DPG_Pegamento cementoso:...) | Length (m) | GrossFootprintArea (m2) | GrossVolume (m3) = NetVolume (m3) = Volumen (m3) | GrossSideArea (m2) = NetSideArea (m2) = Área (m2) | Longitud (m)
3863560 | 1.17 | 0.0117 | 0.00106783 | 0.106783 | 1.165
3890204 | 2.065 | 0.02065 | 0.00188467 | 0.188467 | 2.075

# IfcWallStandardCase: Muro básico:DPG_Rodapie (3)
In: L0
Type - PredefinedType: STANDARD; Material: Azulejo, porcelana, 6 pulg. 0.01 m
Type - Otra - Categoría: Muros; Nombre de familia: Muro básico
Type - Construcción - Envolvente en extremos: Ninguno; Envolvente en inserciones: Sin envolvente; Función: Retención; Anchura: 0.01 m
Type - Gráficos - Color de relleno de detalle bajo: 0
Type - Datos de identidad - Nombre de tipo: DPG_Rodapie
Type - Propiedades analíticas - Absortancia: 0.7; Aspereza: 3; Coeficiente de transferencia de calor (U): 120 kg/K/s3; Masa térmica: 17000 kg/K/s2; Resistencia térmica (R): 0.00833333 s3*K/kg
Type - Pset_WallCommon - ThermalTransmittance: 120 kg/K/s3
BaseQuantities - Width: 0.01 m
Pset_QuantityTakeOff - Reference: DPG_Rodapie; sets with these values: 2
Pset_WallCommon - LoadBearing: no; IsExternal: yes; ExtendToStructure: no; Reference: DPG_Rodapie
Otra - Familia: Muro básico; Familia y tipo: Muro básico: DPG_Rodapie; ID de tipo: 3863832; Tipo: DPG_Rodapie
Restricciones - Relacionado con masa: no; Delimitación de habitación: no; Desfase superior: 0 m; Distancia de extensión de base: 0 m; Distancia de extensión superior: 0 m; La base está enlazada: no; La parte superior está enlazada: no; Línea de ubicación: Cara de acabado: Exterior; Restricción de base: L0; Altura desconectada: 0.1 m; Desfase de base: 0.125654 m
Proceso por fases - Fase de creación: New
Estructura - Estructura: no; Uso estructural: No portante
Definición de sección transversal - Sección transversal: Vertical
Name (Muro básico:DPG_Rodapie:...) | Height (m) | Length (m) | GrossFootprintArea (m2) | GrossVolume (m3) = NetVolume (m3) = Volumen (m3) | GrossSideArea (m2) = NetSideArea (m2) = Área (m2) | Longitud (m)
3863581 | 0.1 | 1.04 | 0.0104 | 0.00104 | 0.104 | 1.035
3890569 | 0.1 | 2.055 | 0.02055 | 0.002055 | 0.2055 | 2.065
3890761 | 0.123554 | 1.03 | 0.0103 | 0.00115581 | 0.115581 | 1.045

# IfcWallStandardCase: Muro básico:DPG_Vidrio (3)
In: L0
Type - PredefinedType: STANDARD; Material: Vidrio 0.01 m
Type - Otra - Categoría: Muros; Nombre de familia: Muro básico
Type - Construcción - Envolvente en extremos: Ninguno; Envolvente en inserciones: Sin envolvente; Función: Retención; Anchura: 0.01 m
Type - Gráficos - Color de relleno de detalle bajo: 0
Type - Datos de identidad - Nombre de tipo: DPG_Vidrio
Type - Propiedades analíticas - Absortancia: 0.7; Aspereza: 3
BaseQuantities - Height: 0.5 m; Width: 0.01 m
Pset_QuantityTakeOff - Reference: DPG_Vidrio; sets with these values: 2
Pset_WallCommon - LoadBearing: no; IsExternal: yes; ExtendToStructure: no; Reference: DPG_Vidrio
Otra - Familia: Muro básico; Familia y tipo: Muro básico: DPG_Vidrio; ID de tipo: 3863836; Tipo: DPG_Vidrio
Restricciones - Relacionado con masa: no; Delimitación de habitación: no; Desfase superior: 0 m; Distancia de extensión de base: 0 m; Distancia de extensión superior: 0 m; La base está enlazada: no; La parte superior está enlazada: no; Restricción de base: L0; Altura desconectada: 0.5 m; Desfase de base: 0.85 m; Línea de ubicación: Eje del muro
Proceso por fases - Fase de creación: New
Estructura - Estructura: no; Uso estructural: No portante
Definición de sección transversal - Sección transversal: Vertical
Name (Muro básico:DPG_Vidrio:...) | Length (m) | GrossFootprintArea (m2) | GrossVolume (m3) = NetVolume (m3) = Volumen (m3) | GrossSideArea (m2) = NetSideArea (m2) = Área (m2) | Longitud (m)
3863561 | 1.445 | 0.01445 | 0.007225 | 0.7225 | 1.44
3883460 | 0.035 | 0.00035 | 0.000175 | 0.0175 | 0.04
3883895 | 2.08 | 0.0208 | 0.0104 | 1.04 | 2.08
